VERSION 5.8 ;
BUSBITCHARS "[]" ;
DIVIDERCHAR "/" ;
 
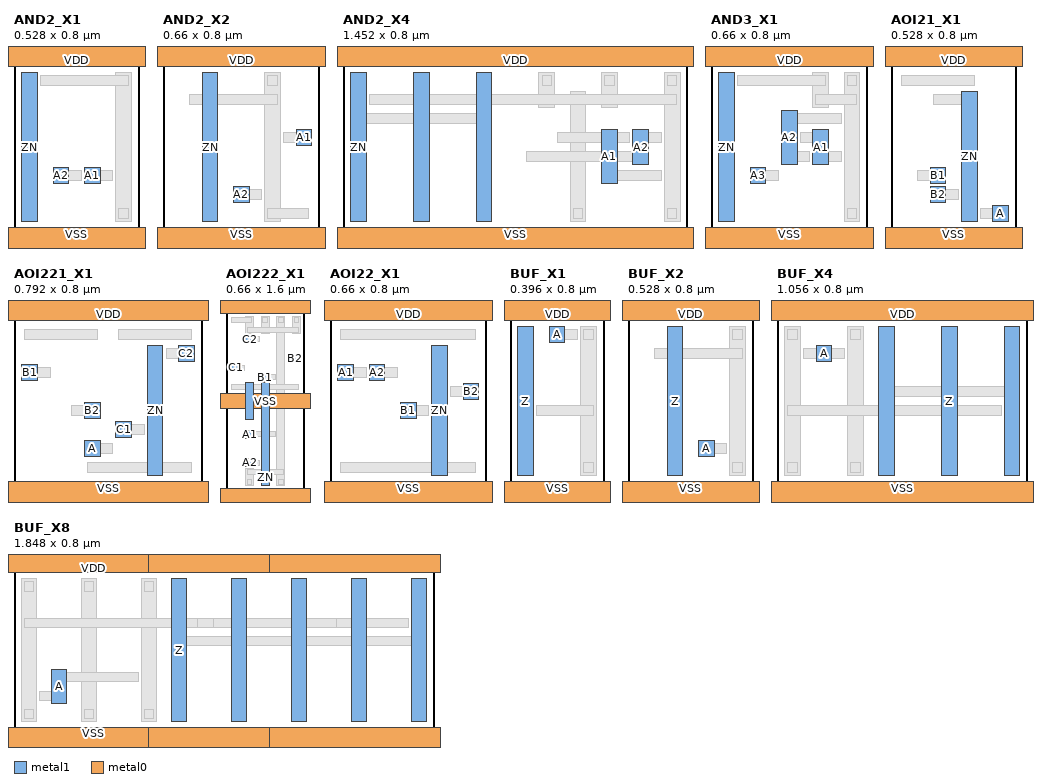
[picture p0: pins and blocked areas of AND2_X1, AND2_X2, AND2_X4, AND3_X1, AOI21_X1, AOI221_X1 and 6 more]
MACRO AND2_X1
  CLASS CORE ;
  FOREIGN AND2_X1 0 0 ;
  SIZE 0.528 BY 0.8 ;
  ORIGIN 0.0 0.0 ;
  SYMMETRY X Y ;
  PIN A1
    DIRECTION INPUT ;
    USE SIGNAL ;
    ANTENNAGATEAREA 0.008640 ;
    PORT
      LAYER metal1 ;
        RECT 0.297 0.247 0.363 0.313 ;
    END
  END A1
  PIN A2
    DIRECTION INPUT ;
    USE SIGNAL ;
    ANTENNAGATEAREA 0.008640 ;
    PORT
      LAYER metal1 ;
        RECT 0.165 0.247 0.231 0.313 ;
    END
  END A2
  PIN ZN
    DIRECTION OUTPUT ;
    USE SIGNAL ;
    ANTENNADIFFAREA 0.03888 ;
    PORT
      LAYER metal1 ;
        RECT 0.033 0.087 0.099 0.713 ;
    END
  END ZN
  PIN VDD
    DIRECTION INOUT ;
    USE POWER ;
    PORT
      LAYER metal0 ;
        RECT -0.066 0.74 0.594 0.86 ;
    END
  END VDD
  PIN VSS
    DIRECTION INOUT ;
    USE GROUND ;
    PORT
      LAYER metal0 ;
        RECT -0.066 -0.06 0.594 0.06 ;
    END
  END VSS
  OBS
    LAYER metal1 ;
      RECT 0.429 0.087 0.495 0.713 ;
    LAYER metal0 ;
      RECT 0.112 0.66 0.482 0.7 ;
      RECT 0.442 0.1 0.482 0.14 ;
      RECT 0.31 0.26 0.416 0.3 ;
      RECT 0.178 0.26 0.284 0.3 ;
      RECT 0.046 0.66 0.086 0.7 ;
      RECT 0.046 0.1 0.086 0.14 ;
  END
END AND2_X1

MACRO AND2_X2
  CLASS CORE ;
  FOREIGN AND2_X2 0 0 ;
  SIZE 0.66 BY 0.8 ;
  ORIGIN 0.0 0.0 ;
  SYMMETRY X Y ;
  PIN A1
    DIRECTION INPUT ;
    USE SIGNAL ;
    ANTENNAGATEAREA 0.008640 ;
    PORT
      LAYER metal1 ;
        RECT 0.561 0.407 0.627 0.473 ;
    END
  END A1
  PIN A2
    DIRECTION INPUT ;
    USE SIGNAL ;
    ANTENNAGATEAREA 0.008640 ;
    PORT
      LAYER metal1 ;
        RECT 0.297 0.167 0.363 0.233 ;
    END
  END A2
  PIN ZN
    DIRECTION OUTPUT ;
    USE SIGNAL ;
    ANTENNADIFFAREA 0.03888 ;
    PORT
      LAYER metal1 ;
        RECT 0.165 0.087 0.231 0.713 ;
    END
  END ZN
  PIN VDD
    DIRECTION INOUT ;
    USE POWER ;
    PORT
      LAYER metal0 ;
        RECT -0.066 0.74 0.726 0.86 ;
    END
  END VDD
  PIN VSS
    DIRECTION INOUT ;
    USE GROUND ;
    PORT
      LAYER metal0 ;
        RECT -0.066 -0.06 0.726 0.06 ;
    END
  END VSS
  OBS
    LAYER metal1 ;
      RECT 0.429 0.087 0.495 0.713 ;
    LAYER metal0 ;
      RECT 0.112 0.58 0.482 0.62 ;
      RECT 0.442 0.1 0.614 0.14 ;
      RECT 0.442 0.66 0.482 0.7 ;
      RECT 0.508 0.42 0.614 0.46 ;
      RECT 0.31 0.18 0.416 0.22 ;
      RECT 0.178 0.66 0.218 0.7 ;
      RECT 0.178 0.1 0.218 0.14 ;
  END
END AND2_X2

MACRO AND2_X4
  CLASS CORE ;
  FOREIGN AND2_X4 0 0 ;
  SIZE 1.452 BY 0.8 ;
  ORIGIN 0.0 0.0 ;
  SYMMETRY X Y ;
  PIN A1
    DIRECTION INPUT ;
    USE SIGNAL ;
    ANTENNAGATEAREA 0.017280 ;
    PORT
      LAYER metal1 ;
        RECT 1.089 0.247 1.155 0.473 ;
    END
  END A1
  PIN A2
    DIRECTION INPUT ;
    USE SIGNAL ;
    ANTENNAGATEAREA 0.017280 ;
    PORT
      LAYER metal1 ;
        RECT 1.221 0.327 1.287 0.473 ;
    END
  END A2
  PIN ZN
    DIRECTION OUTPUT ;
    USE SIGNAL ;
    ANTENNADIFFAREA 0.11664 ;
    PORT
      LAYER metal1 ;
        RECT 0.033 0.087 0.099 0.713 ;
        RECT 0.297 0.087 0.363 0.713 ;
        RECT 0.561 0.087 0.627 0.713 ;
    END
  END ZN
  PIN VDD
    DIRECTION INOUT ;
    USE POWER ;
    PORT
      LAYER metal0 ;
        RECT -0.066 0.74 1.518 0.86 ;
    END
  END VDD
  PIN VSS
    DIRECTION INOUT ;
    USE GROUND ;
    PORT
      LAYER metal0 ;
        RECT -0.066 -0.06 1.518 0.06 ;
    END
  END VSS
  OBS
    LAYER metal1 ;
      RECT 0.825 0.567 0.891 0.713 ;
      RECT 0.957 0.087 1.023 0.633 ;
      RECT 1.089 0.567 1.155 0.713 ;
      RECT 1.353 0.087 1.419 0.713 ;
    LAYER metal0 ;
      RECT 0.112 0.58 1.406 0.62 ;
      RECT 0.838 0.66 0.878 0.7 ;
      RECT 1.102 0.66 1.142 0.7 ;
      RECT 1.366 0.66 1.406 0.7 ;
      RECT 0.97 0.1 1.01 0.14 ;
      RECT 1.366 0.1 1.406 0.14 ;
      RECT 1.102 0.26 1.34 0.3 ;
      RECT 0.904 0.42 1.208 0.46 ;
      RECT 0.772 0.34 1.274 0.38 ;
      RECT 1.234 0.42 1.34 0.46 ;
      RECT 0.046 0.66 0.086 0.7 ;
      RECT 0.046 0.5 0.614 0.54 ;
      RECT 0.046 0.1 0.086 0.14 ;
      RECT 0.574 0.1 0.614 0.14 ;
      RECT 0.31 0.1 0.35 0.14 ;
      RECT 0.31 0.66 0.35 0.7 ;
      RECT 0.574 0.66 0.614 0.7 ;
  END
END AND2_X4

MACRO AND3_X1
  CLASS CORE ;
  FOREIGN AND3_X1 0 0 ;
  SIZE 0.66 BY 0.8 ;
  ORIGIN 0.0 0.0 ;
  SYMMETRY X Y ;
  PIN A1
    DIRECTION INPUT ;
    USE SIGNAL ;
    ANTENNAGATEAREA 0.008640 ;
    PORT
      LAYER metal1 ;
        RECT 0.429 0.327 0.495 0.473 ;
    END
  END A1
  PIN A2
    DIRECTION INPUT ;
    USE SIGNAL ;
    ANTENNAGATEAREA 0.008640 ;
    PORT
      LAYER metal1 ;
        RECT 0.297 0.327 0.363 0.553 ;
    END
  END A2
  PIN A3
    DIRECTION INPUT ;
    USE SIGNAL ;
    ANTENNAGATEAREA 0.008640 ;
    PORT
      LAYER metal1 ;
        RECT 0.165 0.247 0.231 0.313 ;
    END
  END A3
  PIN ZN
    DIRECTION OUTPUT ;
    USE SIGNAL ;
    ANTENNADIFFAREA 0.03888 ;
    PORT
      LAYER metal1 ;
        RECT 0.033 0.087 0.099 0.713 ;
    END
  END ZN
  PIN VDD
    DIRECTION INOUT ;
    USE POWER ;
    PORT
      LAYER metal0 ;
        RECT -0.066 0.74 0.726 0.86 ;
    END
  END VDD
  PIN VSS
    DIRECTION INOUT ;
    USE GROUND ;
    PORT
      LAYER metal0 ;
        RECT -0.066 -0.06 0.726 0.06 ;
    END
  END VSS
  OBS
    LAYER metal1 ;
      RECT 0.429 0.567 0.495 0.713 ;
      RECT 0.561 0.087 0.627 0.713 ;
    LAYER metal0 ;
      RECT 0.112 0.66 0.482 0.7 ;
      RECT 0.442 0.58 0.614 0.62 ;
      RECT 0.574 0.66 0.614 0.7 ;
      RECT 0.574 0.1 0.614 0.14 ;
      RECT 0.442 0.34 0.548 0.38 ;
      RECT 0.376 0.42 0.482 0.46 ;
      RECT 0.31 0.34 0.416 0.38 ;
      RECT 0.31 0.5 0.548 0.54 ;
      RECT 0.178 0.26 0.284 0.3 ;
      RECT 0.046 0.66 0.086 0.7 ;
      RECT 0.046 0.1 0.086 0.14 ;
  END
END AND3_X1

MACRO AOI21_X1
  CLASS CORE ;
  FOREIGN AOI21_X1 0 0 ;
  SIZE 0.528 BY 0.8 ;
  ORIGIN 0.0 0.0 ;
  SYMMETRY X Y ;
  PIN A
    DIRECTION INPUT ;
    USE SIGNAL ;
    ANTENNAGATEAREA 0.008640 ;
    PORT
      LAYER metal1 ;
        RECT 0.429 0.087 0.495 0.153 ;
    END
  END A
  PIN B1
    DIRECTION INPUT ;
    USE SIGNAL ;
    ANTENNAGATEAREA 0.008640 ;
    PORT
      LAYER metal1 ;
        RECT 0.165 0.247 0.231 0.313 ;
    END
  END B1
  PIN B2
    DIRECTION INPUT ;
    USE SIGNAL ;
    ANTENNAGATEAREA 0.008640 ;
    PORT
      LAYER metal1 ;
        RECT 0.165 0.167 0.231 0.233 ;
    END
  END B2
  PIN ZN
    DIRECTION OUTPUT ;
    USE SIGNAL ;
    ANTENNADIFFAREA 0.03888 ;
    PORT
      LAYER metal1 ;
        RECT 0.297 0.087 0.363 0.633 ;
    END
  END ZN
  PIN VDD
    DIRECTION INOUT ;
    USE POWER ;
    PORT
      LAYER metal0 ;
        RECT -0.066 0.74 0.594 0.86 ;
    END
  END VDD
  PIN VSS
    DIRECTION INOUT ;
    USE GROUND ;
    PORT
      LAYER metal0 ;
        RECT -0.066 -0.06 0.594 0.06 ;
    END
  END VSS
  OBS
    LAYER metal0 ;
      RECT 0.046 0.66 0.35 0.7 ;
      RECT 0.376 0.1 0.482 0.14 ;
      RECT 0.112 0.26 0.218 0.3 ;
      RECT 0.178 0.18 0.284 0.22 ;
      RECT 0.31 0.1 0.35 0.14 ;
      RECT 0.178 0.58 0.35 0.62 ;
  END
END AOI21_X1

MACRO AOI221_X1
  CLASS CORE ;
  FOREIGN AOI221_X1 0 0 ;
  SIZE 0.792 BY 0.8 ;
  ORIGIN 0.0 0.0 ;
  SYMMETRY X Y ;
  PIN A
    DIRECTION INPUT ;
    USE SIGNAL ;
    ANTENNAGATEAREA 0.008640 ;
    PORT
      LAYER metal1 ;
        RECT 0.297 0.167 0.363 0.233 ;
    END
  END A
  PIN B1
    DIRECTION INPUT ;
    USE SIGNAL ;
    ANTENNAGATEAREA 0.008640 ;
    PORT
      LAYER metal1 ;
        RECT 0.033 0.487 0.099 0.553 ;
    END
  END B1
  PIN B2
    DIRECTION INPUT ;
    USE SIGNAL ;
    ANTENNAGATEAREA 0.008640 ;
    PORT
      LAYER metal1 ;
        RECT 0.297 0.327 0.363 0.393 ;
    END
  END B2
  PIN C1
    DIRECTION INPUT ;
    USE SIGNAL ;
    ANTENNAGATEAREA 0.008640 ;
    PORT
      LAYER metal1 ;
        RECT 0.429 0.247 0.495 0.313 ;
    END
  END C1
  PIN C2
    DIRECTION INPUT ;
    USE SIGNAL ;
    ANTENNAGATEAREA 0.008640 ;
    PORT
      LAYER metal1 ;
        RECT 0.693 0.567 0.759 0.633 ;
    END
  END C2
  PIN ZN
    DIRECTION OUTPUT ;
    USE SIGNAL ;
    ANTENNADIFFAREA 0.05832 ;
    PORT
      LAYER metal1 ;
        RECT 0.561 0.087 0.627 0.633 ;
    END
  END ZN
  PIN VDD
    DIRECTION INOUT ;
    USE POWER ;
    PORT
      LAYER metal0 ;
        RECT -0.066 0.74 0.858 0.86 ;
    END
  END VDD
  PIN VSS
    DIRECTION INOUT ;
    USE GROUND ;
    PORT
      LAYER metal0 ;
        RECT -0.066 -0.06 0.858 0.06 ;
    END
  END VSS
  OBS
    LAYER metal0 ;
      RECT 0.442 0.66 0.746 0.7 ;
      RECT 0.046 0.66 0.35 0.7 ;
      RECT 0.31 0.18 0.416 0.22 ;
      RECT 0.046 0.5 0.152 0.54 ;
      RECT 0.244 0.34 0.35 0.38 ;
      RECT 0.442 0.26 0.548 0.3 ;
      RECT 0.64 0.58 0.746 0.62 ;
      RECT 0.31 0.1 0.746 0.14 ;
      RECT 0.574 0.58 0.614 0.62 ;
  END
END AOI221_X1

MACRO AOI222_X1
  CLASS CORE ;
  FOREIGN AOI222_X1 0 0 ;
  SIZE 0.66 BY 1.6 ;
  ORIGIN 0.0 0.0 ;
  SYMMETRY X Y ;
  PIN A1
    DIRECTION INPUT ;
    USE SIGNAL ;
    ANTENNAGATEAREA 0.008640 ;
    PORT
      LAYER metal1 ;
        RECT 0.165 0.487 0.231 0.553 ;
    END
  END A1
  PIN A2
    DIRECTION INPUT ;
    USE SIGNAL ;
    ANTENNAGATEAREA 0.008640 ;
    PORT
      LAYER metal1 ;
        RECT 0.165 0.247 0.231 0.313 ;
    END
  END A2
  PIN B1
    DIRECTION INPUT ;
    USE SIGNAL ;
    ANTENNAGATEAREA 0.008640 ;
    PORT
      LAYER metal1 ;
        RECT 0.297 0.967 0.363 1.033 ;
    END
  END B1
  PIN B2
    DIRECTION INPUT ;
    USE SIGNAL ;
    ANTENNAGATEAREA 0.008640 ;
    PORT
      LAYER metal1 ;
        RECT 0.561 1.127 0.627 1.193 ;
    END
  END B2
  PIN C1
    DIRECTION INPUT ;
    USE SIGNAL ;
    ANTENNAGATEAREA 0.008640 ;
    PORT
      LAYER metal1 ;
        RECT 0.033 1.047 0.099 1.113 ;
    END
  END C1
  PIN C2
    DIRECTION INPUT ;
    USE SIGNAL ;
    ANTENNAGATEAREA 0.008640 ;
    PORT
      LAYER metal1 ;
        RECT 0.165 1.287 0.231 1.353 ;
    END
  END C2
  PIN ZN
    DIRECTION OUTPUT ;
    USE SIGNAL ;
    ANTENNADIFFAREA 0.07776 ;
    PORT
      LAYER metal1 ;
        RECT 0.165 0.647 0.231 0.953 ;
        RECT 0.297 0.087 0.363 0.953 ;
    END
  END ZN
  PIN VDD
    DIRECTION INOUT ;
    USE POWER ;
    PORT
      LAYER metal0 ;
        RECT -0.066 -0.06 0.726 0.06 ;
        RECT -0.066 1.54 0.726 1.66 ;
    END
  END VDD
  PIN VSS
    DIRECTION INOUT ;
    USE GROUND ;
    PORT
      LAYER metal0 ;
        RECT -0.066 0.74 0.726 0.86 ;
    END
  END VSS
  OBS
    LAYER metal1 ;
      RECT 0.561 1.367 0.627 1.513 ;
      RECT 0.297 1.367 0.363 1.513 ;
      RECT 0.165 1.367 0.231 1.513 ;
      RECT 0.429 0.087 0.495 1.513 ;
      RECT 0.165 0.087 0.231 0.233 ;
    LAYER metal0 ;
      RECT 0.574 1.46 0.614 1.5 ;
      RECT 0.31 1.46 0.35 1.5 ;
      RECT 0.442 0.1 0.482 0.14 ;
      RECT 0.178 0.1 0.218 0.14 ;
      RECT 0.442 1.46 0.482 1.5 ;
      RECT 0.178 1.38 0.614 1.42 ;
      RECT 0.046 1.46 0.218 1.5 ;
      RECT 0.178 0.18 0.482 0.22 ;
      RECT 0.178 0.5 0.416 0.54 ;
      RECT 0.178 0.26 0.284 0.3 ;
      RECT 0.31 0.98 0.416 1.02 ;
      RECT 0.508 1.14 0.614 1.18 ;
      RECT 0.046 1.06 0.152 1.1 ;
      RECT 0.178 1.3 0.284 1.34 ;
      RECT 0.178 0.66 0.218 0.7 ;
      RECT 0.046 0.9 0.614 0.94 ;
      RECT 0.31 0.1 0.35 0.14 ;
  END
END AOI222_X1

MACRO AOI22_X1
  CLASS CORE ;
  FOREIGN AOI22_X1 0 0 ;
  SIZE 0.66 BY 0.8 ;
  ORIGIN 0.0 0.0 ;
  SYMMETRY X Y ;
  PIN A1
    DIRECTION INPUT ;
    USE SIGNAL ;
    ANTENNAGATEAREA 0.008640 ;
    PORT
      LAYER metal1 ;
        RECT 0.033 0.487 0.099 0.553 ;
    END
  END A1
  PIN A2
    DIRECTION INPUT ;
    USE SIGNAL ;
    ANTENNAGATEAREA 0.008640 ;
    PORT
      LAYER metal1 ;
        RECT 0.165 0.487 0.231 0.553 ;
    END
  END A2
  PIN B1
    DIRECTION INPUT ;
    USE SIGNAL ;
    ANTENNAGATEAREA 0.008640 ;
    PORT
      LAYER metal1 ;
        RECT 0.297 0.327 0.363 0.393 ;
    END
  END B1
  PIN B2
    DIRECTION INPUT ;
    USE SIGNAL ;
    ANTENNAGATEAREA 0.008640 ;
    PORT
      LAYER metal1 ;
        RECT 0.561 0.407 0.627 0.473 ;
    END
  END B2
  PIN ZN
    DIRECTION OUTPUT ;
    USE SIGNAL ;
    ANTENNADIFFAREA 0.05832 ;
    PORT
      LAYER metal1 ;
        RECT 0.429 0.087 0.495 0.633 ;
    END
  END ZN
  PIN VDD
    DIRECTION INOUT ;
    USE POWER ;
    PORT
      LAYER metal0 ;
        RECT -0.066 0.74 0.726 0.86 ;
    END
  END VDD
  PIN VSS
    DIRECTION INOUT ;
    USE GROUND ;
    PORT
      LAYER metal0 ;
        RECT -0.066 -0.06 0.726 0.06 ;
    END
  END VSS
  OBS
    LAYER metal0 ;
      RECT 0.046 0.66 0.614 0.7 ;
      RECT 0.046 0.5 0.152 0.54 ;
      RECT 0.178 0.5 0.284 0.54 ;
      RECT 0.31 0.34 0.416 0.38 ;
      RECT 0.508 0.42 0.614 0.46 ;
      RECT 0.442 0.58 0.482 0.62 ;
      RECT 0.046 0.1 0.614 0.14 ;
  END
END AOI22_X1

MACRO BUF_X1
  CLASS CORE ;
  FOREIGN BUF_X1 0 0 ;
  SIZE 0.396 BY 0.8 ;
  ORIGIN 0.0 0.0 ;
  SYMMETRY X Y ;
  PIN A
    DIRECTION INPUT ;
    USE SIGNAL ;
    ANTENNAGATEAREA 0.008640 ;
    PORT
      LAYER metal1 ;
        RECT 0.165 0.647 0.231 0.713 ;
    END
  END A
  PIN Z
    DIRECTION OUTPUT ;
    USE SIGNAL ;
    ANTENNADIFFAREA 0.03888 ;
    PORT
      LAYER metal1 ;
        RECT 0.033 0.087 0.099 0.713 ;
    END
  END Z
  PIN VDD
    DIRECTION INOUT ;
    USE POWER ;
    PORT
      LAYER metal0 ;
        RECT -0.066 0.74 0.462 0.86 ;
    END
  END VDD
  PIN VSS
    DIRECTION INOUT ;
    USE GROUND ;
    PORT
      LAYER metal0 ;
        RECT -0.066 -0.06 0.462 0.06 ;
    END
  END VSS
  OBS
    LAYER metal1 ;
      RECT 0.297 0.087 0.363 0.713 ;
    LAYER metal0 ;
      RECT 0.112 0.34 0.35 0.38 ;
      RECT 0.31 0.66 0.35 0.7 ;
      RECT 0.31 0.1 0.35 0.14 ;
      RECT 0.178 0.66 0.284 0.7 ;
      RECT 0.046 0.66 0.086 0.7 ;
      RECT 0.046 0.1 0.086 0.14 ;
  END
END BUF_X1

MACRO BUF_X2
  CLASS CORE ;
  FOREIGN BUF_X2 0 0 ;
  SIZE 0.528 BY 0.8 ;
  ORIGIN 0.0 0.0 ;
  SYMMETRY X Y ;
  PIN A
    DIRECTION INPUT ;
    USE SIGNAL ;
    ANTENNAGATEAREA 0.008640 ;
    PORT
      LAYER metal1 ;
        RECT 0.297 0.167 0.363 0.233 ;
    END
  END A
  PIN Z
    DIRECTION OUTPUT ;
    USE SIGNAL ;
    ANTENNADIFFAREA 0.03888 ;
    PORT
      LAYER metal1 ;
        RECT 0.165 0.087 0.231 0.713 ;
    END
  END Z
  PIN VDD
    DIRECTION INOUT ;
    USE POWER ;
    PORT
      LAYER metal0 ;
        RECT -0.066 0.74 0.594 0.86 ;
    END
  END VDD
  PIN VSS
    DIRECTION INOUT ;
    USE GROUND ;
    PORT
      LAYER metal0 ;
        RECT -0.066 -0.06 0.594 0.06 ;
    END
  END VSS
  OBS
    LAYER metal1 ;
      RECT 0.429 0.087 0.495 0.713 ;
    LAYER metal0 ;
      RECT 0.112 0.58 0.482 0.62 ;
      RECT 0.442 0.66 0.482 0.7 ;
      RECT 0.442 0.1 0.482 0.14 ;
      RECT 0.31 0.18 0.416 0.22 ;
      RECT 0.178 0.66 0.218 0.7 ;
      RECT 0.178 0.1 0.218 0.14 ;
  END
END BUF_X2

MACRO BUF_X4
  CLASS CORE ;
  FOREIGN BUF_X4 0 0 ;
  SIZE 1.056 BY 0.8 ;
  ORIGIN 0.0 0.0 ;
  SYMMETRY X Y ;
  PIN A
    DIRECTION INPUT ;
    USE SIGNAL ;
    ANTENNAGATEAREA 0.017280 ;
    PORT
      LAYER metal1 ;
        RECT 0.165 0.567 0.231 0.633 ;
    END
  END A
  PIN Z
    DIRECTION OUTPUT ;
    USE SIGNAL ;
    ANTENNADIFFAREA 0.11664 ;
    PORT
      LAYER metal1 ;
        RECT 0.429 0.087 0.495 0.713 ;
        RECT 0.693 0.087 0.759 0.713 ;
        RECT 0.957 0.087 1.023 0.713 ;
    END
  END Z
  PIN VDD
    DIRECTION INOUT ;
    USE POWER ;
    PORT
      LAYER metal0 ;
        RECT -0.066 0.74 1.122 0.86 ;
    END
  END VDD
  PIN VSS
    DIRECTION INOUT ;
    USE GROUND ;
    PORT
      LAYER metal0 ;
        RECT -0.066 -0.06 1.122 0.06 ;
    END
  END VSS
  OBS
    LAYER metal1 ;
      RECT 0.033 0.087 0.099 0.713 ;
      RECT 0.297 0.087 0.363 0.713 ;
    LAYER metal0 ;
      RECT 0.046 0.34 0.944 0.38 ;
      RECT 0.046 0.66 0.086 0.7 ;
      RECT 0.31 0.66 0.35 0.7 ;
      RECT 0.046 0.1 0.086 0.14 ;
      RECT 0.31 0.1 0.35 0.14 ;
      RECT 0.112 0.58 0.284 0.62 ;
      RECT 0.442 0.1 0.482 0.14 ;
      RECT 0.442 0.66 0.482 0.7 ;
      RECT 0.442 0.42 1.01 0.46 ;
      RECT 0.97 0.66 1.01 0.7 ;
      RECT 0.97 0.1 1.01 0.14 ;
      RECT 0.706 0.66 0.746 0.7 ;
      RECT 0.706 0.1 0.746 0.14 ;
  END
END BUF_X4

MACRO BUF_X8
  CLASS CORE ;
  FOREIGN BUF_X8 0 0 ;
  SIZE 1.848 BY 0.8 ;
  ORIGIN 0.0 0.0 ;
  SYMMETRY X Y ;
  PIN A
    DIRECTION INPUT ;
    USE SIGNAL ;
    ANTENNAGATEAREA 0.034560 ;
    PORT
      LAYER metal1 ;
        RECT 0.165 0.167 0.231 0.313 ;
    END
  END A
  PIN Z
    DIRECTION OUTPUT ;
    USE SIGNAL ;
    ANTENNADIFFAREA 0.19440 ;
    PORT
      LAYER metal1 ;
        RECT 1.749 0.087 1.815 0.713 ;
        RECT 1.221 0.087 1.287 0.713 ;
        RECT 0.693 0.087 0.759 0.713 ;
        RECT 0.957 0.087 1.023 0.713 ;
        RECT 1.485 0.087 1.551 0.713 ;
    END
  END Z
  PIN VDD
    DIRECTION INOUT ;
    USE POWER ;
    PORT
      LAYER metal0 ;
        RECT 1.122 0.74 1.914 0.86 ;
        RECT -0.066 0.74 0.726 0.86 ;
        RECT 0.594 0.74 1.386 0.86 ;
        RECT 1.122 0.74 1.914 0.86 ;
        RECT -0.066 0.74 0.726 0.86 ;
        RECT 0.594 0.74 1.386 0.86 ;
        RECT 1.122 0.74 1.914 0.86 ;
        RECT -0.066 0.74 0.726 0.86 ;
        RECT 0.594 0.74 1.386 0.86 ;
    END
  END VDD
  PIN VSS
    DIRECTION INOUT ;
    USE GROUND ;
    PORT
      LAYER metal0 ;
        RECT 0.594 -0.06 1.386 0.06 ;
        RECT -0.066 -0.06 0.726 0.06 ;
        RECT 1.122 -0.06 1.914 0.06 ;
        RECT 0.594 -0.06 1.386 0.06 ;
        RECT -0.066 -0.06 0.726 0.06 ;
        RECT 1.122 -0.06 1.914 0.06 ;
        RECT 0.594 -0.06 1.386 0.06 ;
        RECT -0.066 -0.06 0.726 0.06 ;
        RECT 1.122 -0.06 1.914 0.06 ;
    END
  END VSS
  OBS
    LAYER metal1 ;
      RECT 0.033 0.087 0.099 0.713 ;
      RECT 0.297 0.087 0.363 0.713 ;
      RECT 0.561 0.087 0.627 0.713 ;
    LAYER metal0 ;
      RECT 1.366 0.5 1.736 0.54 ;
      RECT 0.838 0.5 1.419 0.54 ;
      RECT 0.772 0.5 0.878 0.54 ;
      RECT 0.046 0.66 0.086 0.7 ;
      RECT 0.31 0.66 0.35 0.7 ;
      RECT 0.574 0.66 0.614 0.7 ;
      RECT 0.046 0.1 0.086 0.14 ;
      RECT 0.31 0.1 0.35 0.14 ;
      RECT 0.574 0.1 0.614 0.14 ;
      RECT 0.046 0.5 0.809 0.54 ;
      RECT 0.112 0.18 0.218 0.22 ;
      RECT 0.178 0.26 0.548 0.3 ;
      RECT 1.762 0.66 1.802 0.7 ;
      RECT 0.706 0.42 1.274 0.46 ;
      RECT 1.234 0.42 1.802 0.46 ;
      RECT 1.762 0.1 1.802 0.14 ;
      RECT 0.97 0.1 1.01 0.14 ;
      RECT 1.498 0.1 1.538 0.14 ;
      RECT 1.498 0.66 1.538 0.7 ;
      RECT 0.97 0.66 1.01 0.7 ;
      RECT 0.706 0.1 0.746 0.14 ;
      RECT 0.706 0.66 0.746 0.7 ;
      RECT 1.234 0.1 1.274 0.14 ;
      RECT 1.234 0.66 1.274 0.7 ;
  END
END BUF_X8

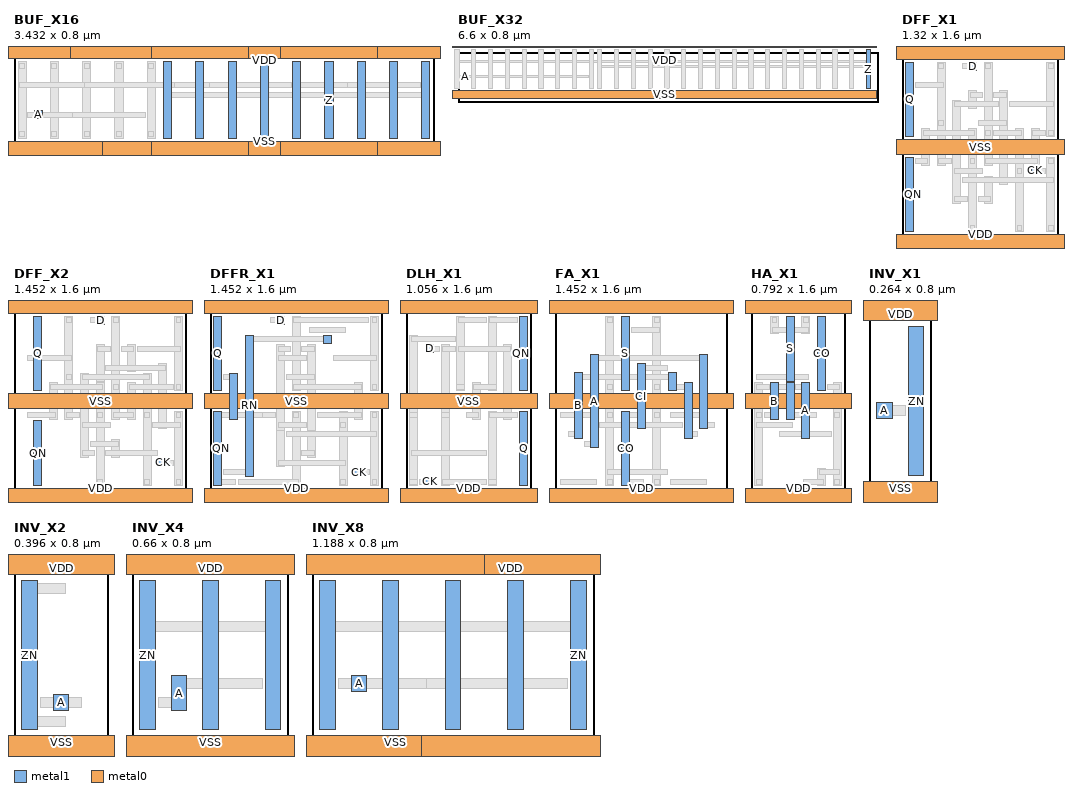
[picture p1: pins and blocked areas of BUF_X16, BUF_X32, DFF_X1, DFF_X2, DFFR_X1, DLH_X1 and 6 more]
MACRO BUF_X16
  CLASS CORE ;
  FOREIGN BUF_X16 0 0 ;
  SIZE 3.432 BY 0.8 ;
  ORIGIN 0.0 0.0 ;
  SYMMETRY X Y ;
  PIN A
    DIRECTION INPUT ;
    USE SIGNAL ;
    ANTENNAGATEAREA 0.069120 ;
    PORT
      LAYER metal1 ;
        RECT 0.165 0.247 0.231 0.313 ;
    END
  END A
  PIN Z
    DIRECTION OUTPUT ;
    USE SIGNAL ;
    ANTENNADIFFAREA 0.34992 ;
    PORT
      LAYER metal1 ;
        RECT 3.333 0.087 3.399 0.713 ;
        RECT 1.749 0.087 1.815 0.713 ;
        RECT 2.541 0.087 2.607 0.713 ;
        RECT 1.485 0.087 1.551 0.713 ;
        RECT 1.221 0.087 1.287 0.713 ;
        RECT 2.013 0.087 2.079 0.713 ;
        RECT 2.805 0.087 2.871 0.713 ;
        RECT 2.277 0.087 2.343 0.713 ;
        RECT 3.069 0.087 3.135 0.713 ;
    END
  END Z
  PIN VDD
    DIRECTION INOUT ;
    USE POWER ;
    PORT
      LAYER metal0 ;
        RECT 1.65 0.74 2.442 0.86 ;
        RECT 2.706 0.74 3.498 0.86 ;
        RECT -0.066 0.74 0.726 0.86 ;
        RECT 0.462 0.74 1.254 0.86 ;
        RECT 1.122 0.74 1.914 0.86 ;
        RECT 2.178 0.74 2.97 0.86 ;
    END
  END VDD
  PIN VSS
    DIRECTION INOUT ;
    USE GROUND ;
    PORT
      LAYER metal0 ;
        RECT 1.65 -0.06 2.442 0.06 ;
        RECT 0.462 -0.06 1.254 0.06 ;
        RECT 2.706 -0.06 3.498 0.06 ;
        RECT 2.178 -0.06 2.97 0.06 ;
        RECT -0.066 -0.06 0.726 0.06 ;
        RECT 1.122 -0.06 1.914 0.06 ;
    END
  END VSS
  OBS
    LAYER metal1 ;
      RECT 0.033 0.087 0.099 0.713 ;
      RECT 0.297 0.087 0.363 0.713 ;
      RECT 0.561 0.087 0.627 0.713 ;
      RECT 1.089 0.087 1.155 0.713 ;
      RECT 0.825 0.087 0.891 0.713 ;
    LAYER metal0 ;
      RECT 2.655 0.5 3.32 0.54 ;
      RECT 2.244 0.5 2.726 0.54 ;
      RECT 1.3 0.5 1.67 0.54 ;
      RECT 1.599 0.5 2.264 0.54 ;
      RECT 0.046 0.1 0.086 0.14 ;
      RECT 0.31 0.1 0.35 0.14 ;
      RECT 0.574 0.1 0.614 0.14 ;
      RECT 0.046 0.66 0.086 0.7 ;
      RECT 0.31 0.66 0.35 0.7 ;
      RECT 0.574 0.66 0.614 0.7 ;
      RECT 0.046 0.5 0.614 0.54 ;
      RECT 1.102 0.1 1.142 0.14 ;
      RECT 0.838 0.1 0.878 0.14 ;
      RECT 1.102 0.66 1.142 0.7 ;
      RECT 0.838 0.66 0.878 0.7 ;
      RECT 0.574 0.5 1.308 0.54 ;
      RECT 0.411 0.26 1.076 0.3 ;
      RECT 0.112 0.26 0.482 0.3 ;
      RECT 1.762 0.42 2.33 0.46 ;
      RECT 3.346 0.1 3.386 0.14 ;
      RECT 1.234 0.42 1.802 0.46 ;
      RECT 3.346 0.66 3.386 0.7 ;
      RECT 2.29 0.42 2.858 0.46 ;
      RECT 2.818 0.42 3.386 0.46 ;
      RECT 1.498 0.1 1.538 0.14 ;
      RECT 1.498 0.66 1.538 0.7 ;
      RECT 1.762 0.1 1.802 0.14 ;
      RECT 1.762 0.66 1.802 0.7 ;
      RECT 3.082 0.66 3.122 0.7 ;
      RECT 3.082 0.1 3.122 0.14 ;
      RECT 2.818 0.66 2.858 0.7 ;
      RECT 2.554 0.1 2.594 0.14 ;
      RECT 2.818 0.1 2.858 0.14 ;
      RECT 2.29 0.66 2.33 0.7 ;
      RECT 1.234 0.1 1.274 0.14 ;
      RECT 2.554 0.66 2.594 0.7 ;
      RECT 1.234 0.66 1.274 0.7 ;
      RECT 2.026 0.66 2.066 0.7 ;
      RECT 2.29 0.1 2.33 0.14 ;
      RECT 2.026 0.1 2.066 0.14 ;
  END
END BUF_X16

MACRO BUF_X32
  CLASS CORE ;
  ORIGIN 0 0 ;
  FOREIGN BUF_X32 0 0 ;
  SIZE 6.6 BY 0.8 ;
  PIN VDD
    DIRECTION INOUT ;
    USE POWER ;
    PORT
      LAYER metal0 ;
        RECT -0.148 0.858 6.584 0.978 ;
    END
  END VDD
  PIN VSS
    DIRECTION INOUT ;
    USE GROUND ;
    PORT
      LAYER metal0 ;
        RECT -0.148 0.058 6.584 0.178 ;
    END
  END VSS
  PIN A
    DIRECTION INOUT ;
    USE SIGNAL ;
    PORT
      LAYER metal1 ;
        RECT 0.083 0.365 0.149 0.431 ;
    END
  END A
  PIN Z
    DIRECTION INOUT ;
    USE SIGNAL ;
    PORT
      LAYER metal1 ;
        RECT 6.419 0.205 6.485 0.831 ;
    END
  END Z
  OBS
    LAYER metal0 SPACING 0 ;
      RECT -0.036 0.218 0.004 0.258 ;
      RECT 0.228 0.218 0.268 0.258 ;
      RECT 0.492 0.218 0.532 0.258 ;
      RECT 0.756 0.218 0.796 0.258 ;
      RECT 1.02 0.218 1.06 0.258 ;
      RECT 1.284 0.218 1.324 0.258 ;
      RECT 1.548 0.218 1.588 0.258 ;
      RECT 1.812 0.218 1.852 0.258 ;
      RECT 2.076 0.218 2.116 0.258 ;
      RECT 2.208 0.218 2.248 0.258 ;
      RECT 2.472 0.218 2.512 0.258 ;
      RECT 2.736 0.218 2.776 0.258 ;
      RECT 3 0.218 3.04 0.258 ;
      RECT 3.264 0.218 3.304 0.258 ;
      RECT 3.528 0.218 3.568 0.258 ;
      RECT 3.792 0.218 3.832 0.258 ;
      RECT 4.056 0.218 4.096 0.258 ;
      RECT 4.32 0.218 4.36 0.258 ;
      RECT 4.584 0.218 4.624 0.258 ;
      RECT 4.848 0.218 4.888 0.258 ;
      RECT 5.112 0.218 5.152 0.258 ;
      RECT 5.376 0.218 5.416 0.258 ;
      RECT 5.64 0.218 5.68 0.258 ;
      RECT 5.904 0.218 5.944 0.258 ;
      RECT 6.168 0.218 6.208 0.258 ;
      RECT 6.432 0.218 6.472 0.258 ;
      RECT 0.03 0.378 2.05 0.418 ;
      RECT 2.208 0.538 6.472 0.578 ;
      RECT -0.036 0.618 6.406 0.658 ;
      RECT -0.036 0.778 0.004 0.818 ;
      RECT 0.228 0.778 0.268 0.818 ;
      RECT 0.492 0.778 0.532 0.818 ;
      RECT 0.756 0.778 0.796 0.818 ;
      RECT 1.02 0.778 1.06 0.818 ;
      RECT 1.284 0.778 1.324 0.818 ;
      RECT 1.548 0.778 1.588 0.818 ;
      RECT 1.812 0.778 1.852 0.818 ;
      RECT 2.076 0.778 2.116 0.818 ;
      RECT 2.208 0.778 2.248 0.818 ;
      RECT 2.472 0.778 2.512 0.818 ;
      RECT 2.736 0.778 2.776 0.818 ;
      RECT 3 0.778 3.04 0.818 ;
      RECT 3.264 0.778 3.304 0.818 ;
      RECT 3.528 0.778 3.568 0.818 ;
      RECT 3.792 0.778 3.832 0.818 ;
      RECT 4.056 0.778 4.096 0.818 ;
      RECT 4.32 0.778 4.36 0.818 ;
      RECT 4.584 0.778 4.624 0.818 ;
      RECT 4.848 0.778 4.888 0.818 ;
      RECT 5.112 0.778 5.152 0.818 ;
      RECT 5.376 0.778 5.416 0.818 ;
      RECT 5.64 0.778 5.68 0.818 ;
      RECT 5.904 0.778 5.944 0.818 ;
      RECT 6.168 0.778 6.208 0.818 ;
      RECT 6.432 0.778 6.472 0.818 ;
    LAYER metal1 SPACING 0 ;
      RECT -0.049 0.205 0.017 0.831 ;
      RECT 0.215 0.205 0.281 0.831 ;
      RECT 0.479 0.205 0.545 0.831 ;
      RECT 0.743 0.205 0.809 0.831 ;
      RECT 1.007 0.205 1.073 0.831 ;
      RECT 1.271 0.205 1.337 0.831 ;
      RECT 1.535 0.205 1.601 0.831 ;
      RECT 1.799 0.205 1.865 0.831 ;
      RECT 2.063 0.205 2.129 0.831 ;
      RECT 2.195 0.205 2.261 0.831 ;
      RECT 2.459 0.205 2.525 0.831 ;
      RECT 2.723 0.205 2.789 0.831 ;
      RECT 2.987 0.205 3.053 0.831 ;
      RECT 3.251 0.205 3.317 0.831 ;
      RECT 3.515 0.205 3.581 0.831 ;
      RECT 3.779 0.205 3.845 0.831 ;
      RECT 4.043 0.205 4.109 0.831 ;
      RECT 4.307 0.205 4.373 0.831 ;
      RECT 4.571 0.205 4.637 0.831 ;
      RECT 4.835 0.205 4.901 0.831 ;
      RECT 5.099 0.205 5.165 0.831 ;
      RECT 5.363 0.205 5.429 0.831 ;
      RECT 5.627 0.205 5.693 0.831 ;
      RECT 5.891 0.205 5.957 0.831 ;
      RECT 6.155 0.205 6.221 0.831 ;
  END
END BUF_X32


MACRO DFF_X1
  CLASS CORE ;
  FOREIGN DFF_X1 0 0 ;
  SIZE 1.32 BY 1.6 ;
  ORIGIN 0.0 0.0 ;
  SYMMETRY X Y ;
  PIN CK
    DIRECTION INPUT ;
    USE CLOCK ;
    ANTENNAGATEAREA 0.008640 ;
    PORT
      LAYER metal1 ;
        RECT 1.089 0.567 1.155 0.633 ;
    END
  END CK
  PIN D
    DIRECTION INPUT ;
    USE SIGNAL ;
    ANTENNAGATEAREA 0.008640 ;
    PORT
      LAYER metal1 ;
        RECT 0.561 1.447 0.627 1.513 ;
    END
  END D
  PIN Q
    DIRECTION OUTPUT ;
    USE SIGNAL ;
    ANTENNADIFFAREA 0.03888 ;
    PORT
      LAYER metal1 ;
        RECT 0.033 0.887 0.099 1.513 ;
    END
  END Q
  PIN QN
    DIRECTION OUTPUT ;
    USE SIGNAL ;
    ANTENNADIFFAREA 0.03888 ;
    PORT
      LAYER metal1 ;
        RECT 0.033 0.087 0.099 0.713 ;
    END
  END QN
  PIN VDD
    DIRECTION INOUT ;
    USE POWER ;
    PORT
      LAYER metal0 ;
        RECT -0.066 1.54 1.386 1.66 ;
        RECT -0.066 -0.06 1.386 0.06 ;
    END
  END VDD
  PIN VSS
    DIRECTION INOUT ;
    USE GROUND ;
    PORT
      LAYER metal0 ;
        RECT -0.066 0.74 1.386 0.86 ;
    END
  END VSS
  OBS
    LAYER metal1 ;
      RECT 0.693 0.647 0.759 1.513 ;
      RECT 1.089 0.647 1.155 0.953 ;
      RECT 0.165 0.647 0.231 0.953 ;
      RECT 0.561 0.087 0.627 0.953 ;
      RECT 0.297 0.647 0.363 1.513 ;
      RECT 0.693 0.327 0.759 0.553 ;
      RECT 0.825 0.487 0.891 1.273 ;
      RECT 1.221 0.087 1.287 0.713 ;
      RECT 0.429 0.327 0.495 1.193 ;
      RECT 0.561 1.127 0.627 1.273 ;
      RECT 0.957 0.087 1.023 0.953 ;
      RECT 1.221 0.887 1.287 1.513 ;
    LAYER metal0 ;
      RECT 1.102 0.9 1.208 0.94 ;
      RECT 0.706 0.66 1.142 0.7 ;
      RECT 0.178 0.9 0.614 0.94 ;
      RECT 0.112 0.66 0.218 0.7 ;
      RECT 0.112 1.3 0.35 1.34 ;
      RECT 0.31 0.66 0.416 0.7 ;
      RECT 0.772 1.22 0.878 1.26 ;
      RECT 0.64 0.98 0.878 1.02 ;
      RECT 0.508 0.5 1.274 0.54 ;
      RECT 0.64 0.34 0.746 0.38 ;
      RECT 0.574 1.22 0.68 1.26 ;
      RECT 0.442 1.14 0.812 1.18 ;
      RECT 0.772 0.9 1.01 0.94 ;
      RECT 0.442 0.58 0.68 0.62 ;
      RECT 0.442 0.34 0.548 0.38 ;
      RECT 0.904 1.14 1.274 1.18 ;
      RECT 0.706 1.46 0.746 1.5 ;
      RECT 0.706 0.9 0.746 0.94 ;
      RECT 0.574 0.66 0.614 0.7 ;
      RECT 0.574 0.1 0.614 0.14 ;
      RECT 0.31 1.46 0.35 1.5 ;
      RECT 0.31 0.98 0.35 1.02 ;
      RECT 1.234 0.66 1.274 0.7 ;
      RECT 1.234 0.1 1.274 0.14 ;
      RECT 0.97 0.58 1.01 0.62 ;
      RECT 0.97 0.1 1.01 0.14 ;
      RECT 1.234 1.46 1.274 1.5 ;
      RECT 1.234 0.9 1.274 0.94 ;
      RECT 1.102 0.58 1.208 0.62 ;
      RECT 0.508 1.46 0.614 1.5 ;
      RECT 0.046 0.9 0.086 0.94 ;
      RECT 0.046 1.46 0.086 1.5 ;
      RECT 0.046 0.66 0.086 0.7 ;
      RECT 0.046 0.1 0.086 0.14 ;
  END
END DFF_X1

MACRO DFF_X2
  CLASS CORE ;
  FOREIGN DFF_X2 0 0 ;
  SIZE 1.452 BY 1.6 ;
  ORIGIN 0.0 0.0 ;
  SYMMETRY X Y ;
  PIN CK
    DIRECTION INPUT ;
    USE CLOCK ;
    ANTENNAGATEAREA 0.008640 ;
    PORT
      LAYER metal1 ;
        RECT 1.221 0.247 1.287 0.313 ;
    END
  END CK
  PIN D
    DIRECTION INPUT ;
    USE SIGNAL ;
    ANTENNAGATEAREA 0.008640 ;
    PORT
      LAYER metal1 ;
        RECT 0.693 1.447 0.759 1.513 ;
    END
  END D
  PIN Q
    DIRECTION OUTPUT ;
    USE SIGNAL ;
    ANTENNADIFFAREA 0.03888 ;
    PORT
      LAYER metal1 ;
        RECT 0.165 0.887 0.231 1.513 ;
    END
  END Q
  PIN QN
    DIRECTION OUTPUT ;
    USE SIGNAL ;
    ANTENNADIFFAREA 0.03888 ;
    PORT
      LAYER metal1 ;
        RECT 0.165 0.087 0.231 0.633 ;
    END
  END QN
  PIN VDD
    DIRECTION INOUT ;
    USE POWER ;
    PORT
      LAYER metal0 ;
        RECT -0.066 1.54 1.518 1.66 ;
        RECT -0.066 -0.06 1.518 0.06 ;
    END
  END VDD
  PIN VSS
    DIRECTION INOUT ;
    USE GROUND ;
    PORT
      LAYER metal0 ;
        RECT -0.066 0.74 1.518 0.86 ;
    END
  END VSS
  OBS
    LAYER metal1 ;
      RECT 0.297 0.647 0.363 0.953 ;
      RECT 0.693 0.087 0.759 0.953 ;
      RECT 0.825 0.647 0.891 1.513 ;
      RECT 0.957 0.647 1.023 0.953 ;
      RECT 0.561 0.327 0.627 1.033 ;
      RECT 0.693 0.967 0.759 1.273 ;
      RECT 1.089 0.087 1.155 1.033 ;
      RECT 1.353 0.887 1.419 1.513 ;
      RECT 0.429 0.647 0.495 1.513 ;
      RECT 0.825 0.327 0.891 0.473 ;
      RECT 0.957 1.047 1.023 1.273 ;
      RECT 1.221 0.567 1.287 1.113 ;
      RECT 1.353 0.087 1.419 0.713 ;
    LAYER metal0 ;
      RECT 0.31 0.9 0.746 0.94 ;
      RECT 0.112 0.66 0.35 0.7 ;
      RECT 0.97 0.9 1.34 0.94 ;
      RECT 0.838 0.66 1.01 0.7 ;
      RECT 0.706 1.22 0.812 1.26 ;
      RECT 0.574 0.98 1.142 1.02 ;
      RECT 0.574 0.58 0.812 0.62 ;
      RECT 0.574 0.34 0.68 0.38 ;
      RECT 1.036 1.22 1.406 1.26 ;
      RECT 0.112 1.14 0.482 1.18 ;
      RECT 0.442 0.66 0.548 0.7 ;
      RECT 0.904 1.22 1.01 1.26 ;
      RECT 0.772 1.06 1.274 1.1 ;
      RECT 1.168 0.58 1.406 0.62 ;
      RECT 0.64 0.42 0.878 0.46 ;
      RECT 0.772 0.34 1.208 0.38 ;
      RECT 0.706 0.66 0.746 0.7 ;
      RECT 0.706 0.1 0.746 0.14 ;
      RECT 0.838 1.46 0.878 1.5 ;
      RECT 0.838 0.9 0.878 0.94 ;
      RECT 1.102 0.66 1.142 0.7 ;
      RECT 1.102 0.1 1.142 0.14 ;
      RECT 1.366 1.46 1.406 1.5 ;
      RECT 1.366 0.9 1.406 0.94 ;
      RECT 0.442 1.46 0.482 1.5 ;
      RECT 0.442 0.98 0.482 1.02 ;
      RECT 1.366 0.66 1.406 0.7 ;
      RECT 1.366 0.1 1.406 0.14 ;
      RECT 1.234 0.26 1.34 0.3 ;
      RECT 0.64 1.46 0.746 1.5 ;
      RECT 0.178 0.9 0.218 0.94 ;
      RECT 0.178 1.46 0.218 1.5 ;
      RECT 0.178 0.1 0.218 0.14 ;
      RECT 0.178 0.58 0.218 0.62 ;
  END
END DFF_X2

MACRO DFFR_X1
  CLASS CORE ;
  FOREIGN DFFR_X1 0 0 ;
  SIZE 1.452 BY 1.6 ;
  ORIGIN 0.0 0.0 ;
  SYMMETRY X Y ;
  PIN CK
    DIRECTION INPUT ;
    USE CLOCK ;
    ANTENNAGATEAREA 0.008640 ;
    PORT
      LAYER metal1 ;
        RECT 1.221 0.167 1.287 0.233 ;
    END
  END CK
  PIN D
    DIRECTION INPUT ;
    USE SIGNAL ;
    ANTENNAGATEAREA 0.008640 ;
    PORT
      LAYER metal1 ;
        RECT 0.561 1.447 0.627 1.513 ;
    END
  END D
  PIN Q
    DIRECTION OUTPUT ;
    USE SIGNAL ;
    ANTENNADIFFAREA 0.03888 ;
    PORT
      LAYER metal1 ;
        RECT 0.033 0.887 0.099 1.513 ;
    END
  END Q
  PIN QN
    DIRECTION OUTPUT ;
    USE SIGNAL ;
    ANTENNAGATEAREA 0.017280 ;
    ANTENNADIFFAREA 0.03888 ;
    PORT
      LAYER metal1 ;
        RECT 0.033 0.087 0.099 0.713 ;
        RECT 0.165 0.647 0.231 1.033 ;
    END
  END QN
  PIN RN
    DIRECTION INPUT ;
    USE SIGNAL ;
    ANTENNAGATEAREA 0.017280 ;
    PORT
      LAYER metal1 ;
        RECT 0.957 1.287 1.023 1.353 ;
        RECT 0.297 0.167 0.363 1.353 ;
    END
  END RN
  PIN VDD
    DIRECTION INOUT ;
    USE POWER ;
    PORT
      LAYER metal0 ;
        RECT -0.066 -0.06 1.518 0.06 ;
        RECT -0.066 1.54 1.518 1.66 ;
    END
  END VDD
  PIN VSS
    DIRECTION INOUT ;
    USE GROUND ;
    PORT
      LAYER metal0 ;
        RECT -0.066 0.74 1.518 0.86 ;
    END
  END VSS
  OBS
    LAYER metal1 ;
      RECT 0.693 0.887 0.759 1.513 ;
      RECT 0.561 0.247 0.627 0.633 ;
      RECT 0.825 0.459 0.891 1.273 ;
      RECT 1.353 0.087 1.419 0.713 ;
      RECT 0.825 0.327 0.891 0.553 ;
      RECT 1.353 0.887 1.419 1.513 ;
      RECT 0.561 0.553 0.627 1.273 ;
      RECT 1.089 0.087 1.155 0.713 ;
      RECT 1.221 0.647 1.287 0.953 ;
      RECT 0.693 0.087 0.759 0.713 ;
    LAYER metal0 ;
      RECT 1.366 1.46 1.406 1.5 ;
      RECT 1.366 0.9 1.406 0.94 ;
      RECT 0.64 0.5 1.406 0.54 ;
      RECT 0.904 0.66 1.274 0.7 ;
      RECT 0.574 0.58 0.812 0.62 ;
      RECT 0.772 0.34 0.878 0.38 ;
      RECT 0.574 0.26 1.143 0.3 ;
      RECT 0.706 0.66 0.746 0.7 ;
      RECT 0.244 0.1 0.746 0.14 ;
      RECT 1.366 0.66 1.406 0.7 ;
      RECT 1.366 0.1 1.406 0.14 ;
      RECT 1.102 0.58 1.142 0.62 ;
      RECT 1.102 0.1 1.142 0.14 ;
      RECT 1.036 1.14 1.406 1.18 ;
      RECT 0.64 0.98 0.878 1.02 ;
      RECT 0.772 1.22 0.878 1.26 ;
      RECT 0.574 1.22 0.68 1.26 ;
      RECT 0.706 1.46 1.332 1.5 ;
      RECT 0.706 0.9 1.274 0.94 ;
      RECT 0.838 1.38 1.143 1.42 ;
      RECT 0.574 1.14 0.811 1.18 ;
      RECT 1.234 0.18 1.34 0.22 ;
      RECT 0.508 1.46 0.614 1.5 ;
      RECT 0.046 0.9 0.086 0.94 ;
      RECT 0.046 1.46 0.086 1.5 ;
      RECT 0.046 0.66 0.482 0.7 ;
      RECT 0.046 0.1 0.218 0.14 ;
      RECT 0.442 0.66 0.548 0.7 ;
      RECT 0.112 0.98 0.218 1.02 ;
      RECT 0.31 1.3 1.011 1.34 ;
      RECT 0.112 0.18 0.35 0.22 ;
  END
END DFFR_X1

MACRO DLH_X1
  CLASS CORE ;
  FOREIGN DLH_X1 0 0 ;
  SIZE 1.056 BY 1.6 ;
  ORIGIN 0.0 0.0 ;
  SYMMETRY X Y ;
  PIN CK
    DIRECTION INPUT ;
    USE CLOCK ;
    ANTENNAGATEAREA 0.008640 ;
    PORT
      LAYER metal1 ;
        RECT 0.165 0.087 0.231 0.153 ;
    END
  END CK
  PIN D
    DIRECTION INPUT ;
    USE SIGNAL ;
    ANTENNAGATEAREA 0.008640 ;
    PORT
      LAYER metal1 ;
        RECT 0.165 1.207 0.231 1.273 ;
    END
  END D
  PIN Q
    DIRECTION OUTPUT ;
    USE SIGNAL ;
    ANTENNADIFFAREA 0.03888 ;
    PORT
      LAYER metal1 ;
        RECT 0.957 0.087 1.023 0.713 ;
    END
  END Q
  PIN QN
    DIRECTION OUTPUT ;
    USE SIGNAL ;
    ANTENNADIFFAREA 0.03888 ;
    PORT
      LAYER metal1 ;
        RECT 0.957 0.887 1.023 1.513 ;
    END
  END QN
  PIN VDD
    DIRECTION INOUT ;
    USE POWER ;
    PORT
      LAYER metal0 ;
        RECT -0.066 -0.06 1.122 0.06 ;
        RECT -0.066 1.54 1.122 1.66 ;
    END
  END VDD
  PIN VSS
    DIRECTION INOUT ;
    USE GROUND ;
    PORT
      LAYER metal0 ;
        RECT -0.066 0.74 1.122 0.86 ;
    END
  END VSS
  OBS
    LAYER metal1 ;
      RECT 0.297 0.087 0.363 1.273 ;
      RECT 0.693 0.087 0.759 0.713 ;
      RECT 0.033 0.087 0.099 1.353 ;
      RECT 0.825 0.647 0.891 1.273 ;
      RECT 0.561 0.642 0.627 0.953 ;
      RECT 0.693 0.887 0.759 1.513 ;
      RECT 0.429 0.887 0.495 1.513 ;
    LAYER metal0 ;
      RECT 0.565 0.9 0.759 0.94 ;
      RECT 0.693 0.1 0.759 0.14 ;
      RECT 0.297 0.66 0.363 0.7 ;
      RECT 0.31 0.1 0.679 0.14 ;
      RECT 0.706 0.66 0.941 0.7 ;
      RECT 0.033 0.66 0.099 0.7 ;
      RECT 0.429 0.9 0.495 0.94 ;
      RECT 0.046 1.3 0.416 1.34 ;
      RECT 0.442 1.22 0.88 1.26 ;
      RECT 0.509 0.66 0.614 0.7 ;
      RECT 0.033 0.1 0.099 0.14 ;
      RECT 0.706 1.46 0.943 1.5 ;
      RECT 0.31 1.22 0.416 1.26 ;
      RECT 0.442 1.46 0.678 1.5 ;
      RECT 0.046 0.34 0.679 0.38 ;
      RECT 0.112 0.1 0.23 0.14 ;
      RECT 0.178 1.22 0.284 1.26 ;
      RECT 0.957 0.66 1.023 0.7 ;
      RECT 0.957 0.1 1.023 0.14 ;
      RECT 0.957 0.9 1.023 0.94 ;
      RECT 0.957 1.46 1.023 1.5 ;
  END
END DLH_X1

MACRO FA_X1
  CLASS CORE ;
  FOREIGN FA_X1 0 0 ;
  SIZE 1.452 BY 1.6 ;
  ORIGIN 0.0 0.0 ;
  SYMMETRY X Y ;
  PIN A
    DIRECTION INPUT ;
    USE SIGNAL ;
    ANTENNAGATEAREA 0.034560 ;
    PORT
      LAYER metal1 ;
        RECT 0.297 0.407 0.363 1.193 ;
        RECT 1.219 0.567 1.285 1.193 ;
    END
  END A
  PIN B
    DIRECTION INPUT ;
    USE SIGNAL ;
    ANTENNAGATEAREA 0.034560 ;
    PORT
      LAYER metal1 ;
        RECT 0.165 0.487 0.231 1.039 ;
        RECT 0.957 0.887 1.023 1.039 ;
        RECT 1.089 0.487 1.155 0.953 ;
    END
  END B
  PIN CI
    DIRECTION INPUT ;
    USE SIGNAL ;
    ANTENNAGATEAREA 0.025920 ;
    PORT
      LAYER metal1 ;
        RECT 0.693 0.567 0.759 1.113 ;
    END
  END CI
  PIN CO
    DIRECTION OUTPUT ;
    USE SIGNAL ;
    ANTENNADIFFAREA 0.03888 ;
    PORT
      LAYER metal1 ;
        RECT 0.561 0.087 0.627 0.713 ;
    END
  END CO
  PIN S
    DIRECTION INPUT ;
    USE SIGNAL ;
    ANTENNADIFFAREA 0.03888 ;
    PORT
      LAYER metal1 ;
        RECT 0.56 0.887 0.626 1.513 ;
    END
  END S
  PIN VDD
    DIRECTION INOUT ;
    USE POWER ;
    PORT
      LAYER metal0 ;
        RECT -0.066 -0.06 1.518 0.06 ;
        RECT -0.066 1.54 1.518 1.66 ;
    END
  END VDD
  PIN VSS
    DIRECTION INOUT ;
    USE GROUND ;
    PORT
      LAYER metal0 ;
        RECT -0.066 0.74 1.518 0.86 ;
    END
  END VSS
  OBS
    LAYER metal1 ;
      RECT 0.825 0.087 0.891 1.513 ;
      RECT 0.429 0.087 0.495 1.513 ;
    LAYER metal0 ;
      RECT 0.046 0.66 0.35 0.7 ;
      RECT 0.97 0.66 1.274 0.7 ;
      RECT 0.838 0.66 0.878 0.7 ;
      RECT 0.838 1.46 0.878 1.5 ;
      RECT 0.442 1.46 0.482 1.5 ;
      RECT 0.838 0.1 0.878 0.14 ;
      RECT 0.046 0.1 0.35 0.14 ;
      RECT 0.97 0.1 1.274 0.14 ;
      RECT 0.442 0.66 0.482 0.7 ;
      RECT 0.64 1.38 0.878 1.42 ;
      RECT 0.442 0.1 0.482 0.14 ;
      RECT 0.442 0.18 0.944 0.22 ;
      RECT 0.838 0.9 0.878 0.94 ;
      RECT 0.442 0.9 0.482 0.94 ;
      RECT 0.25 0.42 0.35 0.46 ;
      RECT 0.31 1.14 1.272 1.18 ;
      RECT 1.233 0.58 1.34 0.62 ;
      RECT 0.112 0.5 0.218 0.54 ;
      RECT 0.178 0.98 1.01 1.02 ;
      RECT 0.97 0.9 1.142 0.94 ;
      RECT 1.102 0.5 1.203 0.54 ;
      RECT 0.705 1.06 0.944 1.1 ;
      RECT 0.376 0.58 1.076 0.62 ;
      RECT 0.574 0.66 0.746 0.7 ;
      RECT 0.574 0.1 0.746 0.14 ;
      RECT 0.574 1.46 0.614 1.5 ;
      RECT 0.574 0.9 0.614 0.94 ;
  END
END FA_X1

MACRO HA_X1
  CLASS CORE ;
  FOREIGN HA_X1 0 0 ;
  SIZE 0.792 BY 1.6 ;
  ORIGIN 0.0 0.0 ;
  SYMMETRY X Y ;
  PIN A
    DIRECTION INPUT ;
    USE SIGNAL ;
    ANTENNAGATEAREA 0.025920 ;
    PORT
      LAYER metal1 ;
        RECT 0.429 0.487 0.495 0.953 ;
    END
  END A
  PIN B
    DIRECTION INPUT ;
    USE SIGNAL ;
    ANTENNAGATEAREA 0.025920 ;
    PORT
      LAYER metal1 ;
        RECT 0.165 0.647 0.231 0.953 ;
        RECT 0.297 0.647 0.363 0.953 ;
    END
  END B
  PIN CO
    DIRECTION OUTPUT ;
    USE SIGNAL ;
    ANTENNADIFFAREA 0.03888 ;
    PORT
      LAYER metal1 ;
        RECT 0.561 0.887 0.627 1.513 ;
    END
  END CO
  PIN S
    DIRECTION INPUT ;
    USE SIGNAL ;
    ANTENNADIFFAREA 0.05832 ;
    PORT
      LAYER metal1 ;
        RECT 0.297 0.967 0.363 1.513 ;
    END
  END S
  PIN VDD
    DIRECTION INOUT ;
    USE POWER ;
    PORT
      LAYER metal0 ;
        RECT -0.066 1.54 0.858 1.66 ;
        RECT -0.066 -0.06 0.858 0.06 ;
    END
  END VDD
  PIN VSS
    DIRECTION INOUT ;
    USE GROUND ;
    PORT
      LAYER metal0 ;
        RECT -0.066 0.74 0.858 0.86 ;
    END
  END VSS
  OBS
    LAYER metal1 ;
      RECT 0.033 0.087 0.099 0.953 ;
      RECT 0.561 0.087 0.627 0.233 ;
      RECT 0.693 0.087 0.759 0.953 ;
      RECT 0.165 1.367 0.231 1.513 ;
      RECT 0.429 1.367 0.495 1.513 ;
    LAYER metal0 ;
      RECT 0.046 0.9 0.152 0.94 ;
      RECT 0.046 0.58 0.35 0.62 ;
      RECT 0.64 0.9 0.746 0.94 ;
      RECT 0.574 0.18 0.746 0.22 ;
      RECT 0.442 0.1 0.614 0.14 ;
      RECT 0.178 1.38 0.482 1.42 ;
      RECT 0.046 0.66 0.086 0.7 ;
      RECT 0.046 0.1 0.086 0.14 ;
      RECT 0.706 0.66 0.746 0.7 ;
      RECT 0.706 0.1 0.746 0.14 ;
      RECT 0.178 1.46 0.218 1.5 ;
      RECT 0.442 1.46 0.482 1.5 ;
      RECT 0.244 0.5 0.68 0.54 ;
      RECT 0.376 0.9 0.482 0.94 ;
      RECT 0.178 0.9 0.35 0.94 ;
      RECT 0.112 0.66 0.218 0.7 ;
      RECT 0.31 0.66 0.548 0.7 ;
      RECT 0.574 1.46 0.614 1.5 ;
      RECT 0.574 0.9 0.614 0.94 ;
      RECT 0.31 1.46 0.35 1.5 ;
      RECT 0.046 0.98 0.482 1.02 ;
  END
END HA_X1

MACRO INV_X1
  CLASS CORE ;
  FOREIGN INV_X1 0 0 ;
  SIZE 0.264 BY 0.8 ;
  ORIGIN 0.0 0.0 ;
  SYMMETRY X Y ;
  PIN A
    DIRECTION INPUT ;
    USE SIGNAL ;
    ANTENNAGATEAREA 0.008640 ;
    PORT
      LAYER metal1 ;
        RECT 0.033 0.327 0.099 0.393 ;
    END
  END A
  PIN ZN
    DIRECTION OUTPUT ;
    USE SIGNAL ;
    ANTENNADIFFAREA 0.03888 ;
    PORT
      LAYER metal1 ;
        RECT 0.165 0.087 0.231 0.713 ;
    END
  END ZN
  PIN VDD
    DIRECTION INOUT ;
    USE POWER ;
    PORT
      LAYER metal0 ;
        RECT -0.066 0.74 0.33 0.86 ;
    END
  END VDD
  PIN VSS
    DIRECTION INOUT ;
    USE GROUND ;
    PORT
      LAYER metal0 ;
        RECT -0.066 -0.06 0.33 0.06 ;
    END
  END VSS
  OBS
    LAYER metal0 ;
      RECT 0.046 0.34 0.152 0.38 ;
      RECT 0.178 0.66 0.218 0.7 ;
      RECT 0.178 0.1 0.218 0.14 ;
  END
END INV_X1

MACRO INV_X2
  CLASS CORE ;
  FOREIGN INV_X2 0 0 ;
  SIZE 0.396 BY 0.8 ;
  ORIGIN 0.0 0.0 ;
  SYMMETRY X Y ;
  PIN A
    DIRECTION INPUT ;
    USE SIGNAL ;
    ANTENNAGATEAREA 0.017280 ;
    PORT
      LAYER metal1 ;
        RECT 0.165 0.167 0.231 0.233 ;
    END
  END A
  PIN ZN
    DIRECTION OUTPUT ;
    USE SIGNAL ;
    ANTENNADIFFAREA 0.03888 ;
    PORT
      LAYER metal1 ;
        RECT 0.033 0.087 0.099 0.713 ;
    END
  END ZN
  PIN VDD
    DIRECTION INOUT ;
    USE POWER ;
    PORT
      LAYER metal0 ;
        RECT -0.066 0.74 0.462 0.86 ;
    END
  END VDD
  PIN VSS
    DIRECTION INOUT ;
    USE GROUND ;
    PORT
      LAYER metal0 ;
        RECT -0.066 -0.06 0.462 0.06 ;
    END
  END VSS
  OBS
    LAYER metal0 ;
      RECT 0.112 0.18 0.284 0.22 ;
      RECT 0.046 0.1 0.218 0.14 ;
      RECT 0.046 0.66 0.218 0.7 ;
  END
END INV_X2

MACRO INV_X4
  CLASS CORE ;
  FOREIGN INV_X4 0 0 ;
  SIZE 0.66 BY 0.8 ;
  ORIGIN 0.0 0.0 ;
  SYMMETRY X Y ;
  PIN A
    DIRECTION INPUT ;
    USE SIGNAL ;
    ANTENNAGATEAREA 0.034560 ;
    PORT
      LAYER metal1 ;
        RECT 0.165 0.167 0.231 0.313 ;
    END
  END A
  PIN ZN
    DIRECTION OUTPUT ;
    USE SIGNAL ;
    ANTENNADIFFAREA 0.11664 ;
    PORT
      LAYER metal1 ;
        RECT 0.033 0.087 0.099 0.713 ;
        RECT 0.297 0.087 0.363 0.713 ;
        RECT 0.561 0.087 0.627 0.713 ;
    END
  END ZN
  PIN VDD
    DIRECTION INOUT ;
    USE POWER ;
    PORT
      LAYER metal0 ;
        RECT -0.066 0.74 0.726 0.86 ;
    END
  END VDD
  PIN VSS
    DIRECTION INOUT ;
    USE GROUND ;
    PORT
      LAYER metal0 ;
        RECT -0.066 -0.06 0.726 0.06 ;
    END
  END VSS
  OBS
    LAYER metal0 ;
      RECT 0.112 0.18 0.218 0.22 ;
      RECT 0.178 0.26 0.548 0.3 ;
      RECT 0.046 0.66 0.086 0.7 ;
      RECT 0.046 0.5 0.614 0.54 ;
      RECT 0.046 0.1 0.086 0.14 ;
      RECT 0.574 0.1 0.614 0.14 ;
      RECT 0.31 0.1 0.35 0.14 ;
      RECT 0.31 0.66 0.35 0.7 ;
      RECT 0.574 0.66 0.614 0.7 ;
  END
END INV_X4

MACRO INV_X8
  CLASS CORE ;
  FOREIGN INV_X8 0 0 ;
  SIZE 1.188 BY 0.8 ;
  ORIGIN 0.0 0.0 ;
  SYMMETRY X Y ;
  PIN A
    DIRECTION INPUT ;
    USE SIGNAL ;
    ANTENNAGATEAREA 0.069120 ;
    PORT
      LAYER metal1 ;
        RECT 0.165 0.247 0.231 0.313 ;
    END
  END A
  PIN ZN
    DIRECTION OUTPUT ;
    USE SIGNAL ;
    ANTENNADIFFAREA 0.19440 ;
    PORT
      LAYER metal1 ;
        RECT 0.561 0.087 0.627 0.713 ;
        RECT 0.297 0.087 0.363 0.713 ;
        RECT 0.033 0.087 0.099 0.713 ;
        RECT 1.089 0.087 1.155 0.713 ;
        RECT 0.825 0.087 0.891 0.713 ;
    END
  END ZN
  PIN VDD
    DIRECTION INOUT ;
    USE POWER ;
    PORT
      LAYER metal0 ;
        RECT 0.462 0.74 1.254 0.86 ;
        RECT -0.066 0.74 0.726 0.86 ;
    END
  END VDD
  PIN VSS
    DIRECTION INOUT ;
    USE GROUND ;
    PORT
      LAYER metal0 ;
        RECT -0.066 -0.06 0.726 0.06 ;
        RECT 0.462 -0.06 1.254 0.06 ;
    END
  END VSS
  OBS
    LAYER metal0 ;
      RECT 0.411 0.26 1.076 0.3 ;
      RECT 0.112 0.26 0.482 0.3 ;
      RECT 0.574 0.5 1.142 0.54 ;
      RECT 0.574 0.1 0.614 0.14 ;
      RECT 0.046 0.5 0.614 0.54 ;
      RECT 0.574 0.66 0.614 0.7 ;
      RECT 0.046 0.66 0.086 0.7 ;
      RECT 0.31 0.1 0.35 0.14 ;
      RECT 1.102 0.1 1.142 0.14 ;
      RECT 0.31 0.66 0.35 0.7 ;
      RECT 1.102 0.66 1.142 0.7 ;
      RECT 0.046 0.1 0.086 0.14 ;
      RECT 0.838 0.66 0.878 0.7 ;
      RECT 0.838 0.1 0.878 0.14 ;
  END
END INV_X8

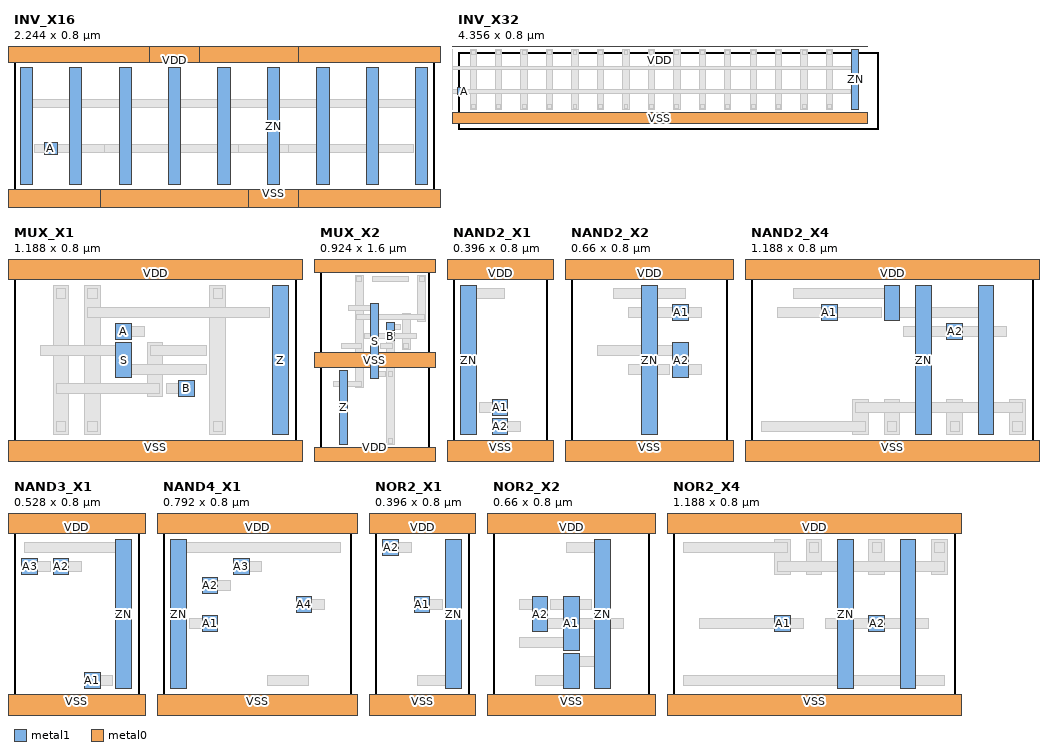
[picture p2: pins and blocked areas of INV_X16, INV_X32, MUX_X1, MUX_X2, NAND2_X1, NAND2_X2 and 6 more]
MACRO INV_X16
  CLASS CORE ;
  FOREIGN INV_X16 0 0 ;
  SIZE 2.244 BY 0.8 ;
  ORIGIN 0.0 0.0 ;
  SYMMETRY X Y ;
  PIN A
    DIRECTION INPUT ;
    USE SIGNAL ;
    ANTENNAGATEAREA 0.138240 ;
    PORT
      LAYER metal1 ;
        RECT 0.164 0.247 0.23 0.313 ;
    END
  END A
  PIN ZN
    DIRECTION OUTPUT ;
    USE SIGNAL ;
    ANTENNADIFFAREA 0.34992 ;
    PORT
      LAYER metal1 ;
        RECT 2.145 0.087 2.211 0.713 ;
        RECT 0.297 0.087 0.363 0.713 ;
        RECT 1.353 0.087 1.419 0.713 ;
        RECT 1.881 0.087 1.947 0.713 ;
        RECT 0.033 0.087 0.099 0.713 ;
        RECT 1.089 0.087 1.155 0.713 ;
        RECT 0.825 0.087 0.891 0.713 ;
        RECT 0.561 0.087 0.627 0.713 ;
        RECT 1.617 0.087 1.683 0.713 ;
    END
  END ZN
  PIN VDD
    DIRECTION INOUT ;
    USE POWER ;
    PORT
      LAYER metal0 ;
        RECT 0.462 0.74 1.254 0.86 ;
        RECT -0.066 0.74 0.726 0.86 ;
        RECT 0.99 0.74 1.782 0.86 ;
        RECT 1.518 0.74 2.31 0.86 ;
    END
  END VDD
  PIN VSS
    DIRECTION INOUT ;
    USE GROUND ;
    PORT
      LAYER metal0 ;
        RECT 0.99 -0.06 1.782 0.06 ;
        RECT -0.066 -0.06 0.726 0.06 ;
        RECT 1.518 -0.06 2.31 0.06 ;
        RECT 0.462 -0.06 1.254 0.06 ;
    END
  END VSS
  OBS
    LAYER metal0 ;
      RECT 1.168 0.26 1.538 0.3 ;
      RECT 1.467 0.26 2.132 0.3 ;
      RECT 0.411 0.26 1.2 0.3 ;
      RECT 0.112 0.26 0.482 0.3 ;
      RECT 1.63 0.5 2.198 0.54 ;
      RECT 1.102 0.5 1.67 0.54 ;
      RECT 2.158 0.66 2.198 0.7 ;
      RECT 0.046 0.5 0.614 0.54 ;
      RECT 2.158 0.1 2.198 0.14 ;
      RECT 0.574 0.5 1.142 0.54 ;
      RECT 1.366 0.66 1.406 0.7 ;
      RECT 0.046 0.66 0.086 0.7 ;
      RECT 0.31 0.1 0.35 0.14 ;
      RECT 1.102 0.1 1.142 0.14 ;
      RECT 1.63 0.1 1.67 0.14 ;
      RECT 0.31 0.66 0.35 0.7 ;
      RECT 1.102 0.66 1.142 0.7 ;
      RECT 0.046 0.1 0.086 0.14 ;
      RECT 1.894 0.66 1.934 0.7 ;
      RECT 1.894 0.1 1.934 0.14 ;
      RECT 1.366 0.1 1.406 0.14 ;
      RECT 0.574 0.66 0.614 0.7 ;
      RECT 0.574 0.1 0.614 0.14 ;
      RECT 0.838 0.66 0.878 0.7 ;
      RECT 1.63 0.66 1.67 0.7 ;
      RECT 0.838 0.1 0.878 0.14 ;
  END
END INV_X16

MACRO INV_X32
  CLASS CORE ;
  ORIGIN 0 0 ;
  FOREIGN INV_X32 0 0 ;
  SIZE 4.356 BY 0.8 ;
  PIN VDD
    DIRECTION INOUT ;
    USE POWER ;
    PORT
      LAYER metal0 ;
        RECT -0.238 0.853 4.25 0.973 ;
    END
  END VDD
  PIN VSS
    DIRECTION INOUT ;
    USE GROUND ;
    PORT
      LAYER metal0 ;
        RECT -0.238 0.053 4.25 0.173 ;
    END
  END VSS
  PIN A
    DIRECTION INOUT ;
    USE SIGNAL ;
    PORT
      LAYER metal1 ;
        RECT -0.008 0.36 0.058 0.426 ;
    END
  END A
  PIN ZN
    DIRECTION INOUT ;
    USE SIGNAL ;
    PORT
      LAYER metal1 ;
        RECT 4.085 0.2 4.151 0.826 ;
    END
  END ZN
  OBS
    LAYER metal1 SPACING 0 ;
      RECT -0.139 0.2 -0.073 0.826 ;
      RECT 0.125 0.2 0.191 0.826 ;
      RECT 0.389 0.2 0.455 0.826 ;
      RECT 0.653 0.2 0.719 0.826 ;
      RECT 0.917 0.2 0.983 0.826 ;
      RECT 1.181 0.2 1.247 0.826 ;
      RECT 1.445 0.2 1.511 0.826 ;
      RECT 1.709 0.2 1.775 0.826 ;
      RECT 1.973 0.2 2.039 0.826 ;
      RECT 2.237 0.2 2.303 0.826 ;
      RECT 2.501 0.2 2.567 0.826 ;
      RECT 2.765 0.2 2.831 0.826 ;
      RECT 3.029 0.2 3.095 0.826 ;
      RECT 3.293 0.2 3.359 0.826 ;
      RECT 3.557 0.2 3.623 0.826 ;
      RECT 3.821 0.2 3.887 0.826 ;
    LAYER metal0 SPACING 0 ;
      RECT -0.126 0.213 -0.086 0.253 ;
      RECT 0.138 0.213 0.178 0.253 ;
      RECT 0.402 0.213 0.442 0.253 ;
      RECT 0.666 0.213 0.706 0.253 ;
      RECT 0.93 0.213 0.97 0.253 ;
      RECT 1.194 0.213 1.234 0.253 ;
      RECT 1.458 0.213 1.498 0.253 ;
      RECT 1.722 0.213 1.762 0.253 ;
      RECT 1.986 0.213 2.026 0.253 ;
      RECT 2.25 0.213 2.29 0.253 ;
      RECT 2.514 0.213 2.554 0.253 ;
      RECT 2.778 0.213 2.818 0.253 ;
      RECT 3.042 0.213 3.082 0.253 ;
      RECT 3.306 0.213 3.346 0.253 ;
      RECT 3.57 0.213 3.61 0.253 ;
      RECT 3.834 0.213 3.874 0.253 ;
      RECT 4.098 0.213 4.138 0.253 ;
      RECT -0.06 0.373 4.072 0.413 ;
      RECT -0.126 0.613 4.138 0.653 ;
      RECT -0.126 0.773 -0.086 0.813 ;
      RECT 0.138 0.773 0.178 0.813 ;
      RECT 0.402 0.773 0.442 0.813 ;
      RECT 0.666 0.773 0.706 0.813 ;
      RECT 0.93 0.773 0.97 0.813 ;
      RECT 1.194 0.773 1.234 0.813 ;
      RECT 1.458 0.773 1.498 0.813 ;
      RECT 1.722 0.773 1.762 0.813 ;
      RECT 1.986 0.773 2.026 0.813 ;
      RECT 2.25 0.773 2.29 0.813 ;
      RECT 2.514 0.773 2.554 0.813 ;
      RECT 2.778 0.773 2.818 0.813 ;
      RECT 3.042 0.773 3.082 0.813 ;
      RECT 3.306 0.773 3.346 0.813 ;
      RECT 3.57 0.773 3.61 0.813 ;
      RECT 3.834 0.773 3.874 0.813 ;
      RECT 4.098 0.773 4.138 0.813 ;
  END
END INV_X32



MACRO MUX_X1
  CLASS CORE ;
  FOREIGN MUX_X1 0 0 ;
  SIZE 1.188 BY 0.8 ;
  ORIGIN 0.0 0.0 ;
  SYMMETRY X Y ;
  PIN A
    DIRECTION INPUT ;
    USE SIGNAL ;
    ANTENNAGATEAREA 0.008640 ;
    PORT
      LAYER metal1 ;
        RECT 0.429 0.487 0.495 0.553 ;
    END
  END A
  PIN B
    DIRECTION INPUT ;
    USE SIGNAL ;
    ANTENNAGATEAREA 0.008640 ;
    PORT
      LAYER metal1 ;
        RECT 0.693 0.247 0.759 0.313 ;
    END
  END B
  PIN S
    DIRECTION INPUT ;
    USE SIGNAL ;
    ANTENNAGATEAREA 0.017280 ;
    PORT
      LAYER metal1 ;
        RECT 0.429 0.327 0.495 0.473 ;
    END
  END S
  PIN Z
    DIRECTION OUTPUT ;
    USE SIGNAL ;
    ANTENNADIFFAREA 0.03888 ;
    PORT
      LAYER metal1 ;
        RECT 1.089 0.087 1.155 0.713 ;
    END
  END Z
  PIN VDD
    DIRECTION INOUT ;
    USE POWER ;
    PORT
      LAYER metal0 ;
        RECT -0.066 0.74 1.254 0.86 ;
    END
  END VDD
  PIN VSS
    DIRECTION INOUT ;
    USE GROUND ;
    PORT
      LAYER metal0 ;
        RECT -0.066 -0.06 1.254 0.06 ;
    END
  END VSS
  OBS
    LAYER metal1 ;
      RECT 0.165 0.087 0.231 0.713 ;
      RECT 0.561 0.247 0.627 0.473 ;
      RECT 0.297 0.087 0.363 0.713 ;
      RECT 0.825 0.087 0.891 0.713 ;
    LAYER metal0 ;
      RECT 0.574 0.42 0.812 0.46 ;
      RECT 0.178 0.26 0.614 0.3 ;
      RECT 0.31 0.58 1.076 0.62 ;
      RECT 0.178 0.66 0.218 0.7 ;
      RECT 0.178 0.1 0.218 0.14 ;
      RECT 0.31 0.66 0.35 0.7 ;
      RECT 0.838 0.66 0.878 0.7 ;
      RECT 0.31 0.1 0.35 0.14 ;
      RECT 0.838 0.1 0.878 0.14 ;
      RECT 0.442 0.5 0.548 0.54 ;
      RECT 0.64 0.26 0.746 0.3 ;
      RECT 0.442 0.34 0.812 0.38 ;
      RECT 0.112 0.42 0.482 0.46 ;
      RECT 1.102 0.1 1.142 0.14 ;
      RECT 1.102 0.66 1.142 0.7 ;
  END
END MUX_X1

MACRO MUX_X2
  CLASS CORE ;
  FOREIGN MUX_X2 0 0 ;
  SIZE 0.924 BY 1.6 ;
  ORIGIN 0.0 0.0 ;
  SYMMETRY X Y ;
  PIN A
    DIRECTION INPUT ;
    USE SIGNAL ;
    ANTENNAGATEAREA 0.008640 ;
    PORT
      LAYER metal1 ;
        RECT 0.561 1.047 0.627 1.113 ;
    END
  END A
  PIN B
    DIRECTION INPUT ;
    USE SIGNAL ;
    ANTENNAGATEAREA 0.012960 ;
    PORT
      LAYER metal1 ;
        RECT 0.561 0.967 0.627 1.033 ;
    END
  END B
  PIN S
    DIRECTION INPUT ;
    USE SIGNAL ;
    ANTENNAGATEAREA 0.021600 ;
    PORT
      LAYER metal1 ;
        RECT 0.429 0.647 0.495 1.273 ;
    END
  END S
  PIN Z
    DIRECTION OUTPUT ;
    USE SIGNAL ;
    ANTENNADIFFAREA 0.03888 ;
    PORT
      LAYER metal1 ;
        RECT 0.165 0.087 0.231 0.713 ;
    END
  END Z
  PIN VDD
    DIRECTION INOUT ;
    USE POWER ;
    PORT
      LAYER metal0 ;
        RECT -0.066 1.54 0.99 1.66 ;
        RECT -0.066 -0.06 0.99 0.06 ;
    END
  END VDD
  PIN VSS
    DIRECTION INOUT ;
    USE GROUND ;
    PORT
      LAYER metal0 ;
        RECT -0.066 0.74 0.99 0.86 ;
    END
  END VSS
  OBS
    LAYER metal1 ;
      RECT 0.561 0.087 0.627 0.953 ;
      RECT 0.297 0.567 0.363 1.513 ;
      RECT 0.693 0.887 0.759 1.193 ;
      RECT 0.825 1.127 0.891 1.513 ;
    LAYER metal0 ;
      RECT 0.508 0.9 0.614 0.94 ;
      RECT 0.31 1.14 0.878 1.18 ;
      RECT 0.178 0.9 0.35 0.94 ;
      RECT 0.112 0.58 0.35 0.62 ;
      RECT 0.442 1.46 0.746 1.5 ;
      RECT 0.574 0.66 0.614 0.7 ;
      RECT 0.574 0.1 0.614 0.14 ;
      RECT 0.31 1.46 0.35 1.5 ;
      RECT 0.838 1.46 0.878 1.5 ;
      RECT 0.706 0.9 0.746 0.94 ;
      RECT 0.574 1.06 0.68 1.1 ;
      RECT 0.376 0.98 0.812 1.02 ;
      RECT 0.244 1.22 0.482 1.26 ;
      RECT 0.442 0.66 0.548 0.7 ;
      RECT 0.178 0.66 0.218 0.7 ;
      RECT 0.178 0.1 0.218 0.14 ;
  END
END MUX_X2

MACRO NAND2_X1
  CLASS CORE ;
  FOREIGN NAND2_X1 0 0 ;
  SIZE 0.396 BY 0.8 ;
  ORIGIN 0.0 0.0 ;
  SYMMETRY X Y ;
  PIN A1
    DIRECTION INPUT ;
    USE SIGNAL ;
    ANTENNAGATEAREA 0.008640 ;
    PORT
      LAYER metal1 ;
        RECT 0.165 0.167 0.231 0.233 ;
    END
  END A1
  PIN A2
    DIRECTION INPUT ;
    USE SIGNAL ;
    ANTENNAGATEAREA 0.008640 ;
    PORT
      LAYER metal1 ;
        RECT 0.165 0.087 0.231 0.153 ;
    END
  END A2
  PIN ZN
    DIRECTION OUTPUT ;
    USE SIGNAL ;
    ANTENNADIFFAREA 0.03888 ;
    PORT
      LAYER metal1 ;
        RECT 0.033 0.087 0.099 0.713 ;
    END
  END ZN
  PIN VDD
    DIRECTION INOUT ;
    USE POWER ;
    PORT
      LAYER metal0 ;
        RECT -0.066 0.74 0.462 0.86 ;
    END
  END VDD
  PIN VSS
    DIRECTION INOUT ;
    USE GROUND ;
    PORT
      LAYER metal0 ;
        RECT -0.066 -0.06 0.462 0.06 ;
    END
  END VSS
  OBS
    LAYER metal0 ;
      RECT 0.112 0.18 0.218 0.22 ;
      RECT 0.178 0.1 0.284 0.14 ;
      RECT 0.046 0.66 0.218 0.7 ;
      RECT 0.046 0.1 0.086 0.14 ;
  END
END NAND2_X1

MACRO NAND2_X2
  CLASS CORE ;
  FOREIGN NAND2_X2 0 0 ;
  SIZE 0.66 BY 0.8 ;
  ORIGIN 0.0 0.0 ;
  SYMMETRY X Y ;
  PIN A1
    DIRECTION INPUT ;
    USE SIGNAL ;
    ANTENNAGATEAREA 0.012960 ;
    PORT
      LAYER metal1 ;
        RECT 0.429 0.567 0.495 0.633 ;
    END
  END A1
  PIN A2
    DIRECTION INPUT ;
    USE SIGNAL ;
    ANTENNAGATEAREA 0.017280 ;
    PORT
      LAYER metal1 ;
        RECT 0.429 0.327 0.495 0.473 ;
    END
  END A2
  PIN ZN
    DIRECTION OUTPUT ;
    USE SIGNAL ;
    ANTENNADIFFAREA 0.05832 ;
    PORT
      LAYER metal1 ;
        RECT 0.297 0.087 0.363 0.713 ;
    END
  END ZN
  PIN VDD
    DIRECTION INOUT ;
    USE POWER ;
    PORT
      LAYER metal0 ;
        RECT -0.066 0.74 0.726 0.86 ;
    END
  END VDD
  PIN VSS
    DIRECTION INOUT ;
    USE GROUND ;
    PORT
      LAYER metal0 ;
        RECT -0.066 -0.06 0.726 0.06 ;
    END
  END VSS
  OBS
    LAYER metal0 ;
      RECT 0.244 0.34 0.416 0.38 ;
      RECT 0.244 0.58 0.548 0.62 ;
      RECT 0.442 0.34 0.548 0.38 ;
      RECT 0.112 0.42 0.482 0.46 ;
      RECT 0.31 0.1 0.35 0.14 ;
      RECT 0.178 0.66 0.482 0.7 ;
  END
END NAND2_X2

MACRO NAND2_X4
  CLASS CORE ;
  FOREIGN NAND2_X4 0 0 ;
  SIZE 1.188 BY 0.8 ;
  ORIGIN 0.0 0.0 ;
  SYMMETRY X Y ;
  PIN A1
    DIRECTION INPUT ;
    USE SIGNAL ;
    ANTENNAGATEAREA 0.034560 ;
    PORT
      LAYER metal1 ;
        RECT 0.297 0.567 0.363 0.633 ;
    END
  END A1
  PIN A2
    DIRECTION INPUT ;
    USE SIGNAL ;
    ANTENNAGATEAREA 0.034560 ;
    PORT
      LAYER metal1 ;
        RECT 0.825 0.487 0.891 0.553 ;
    END
  END A2
  PIN ZN
    DIRECTION OUTPUT ;
    USE SIGNAL ;
    ANTENNADIFFAREA 0.11664 ;
    PORT
      LAYER metal1 ;
        RECT 0.561 0.567 0.627 0.713 ;
        RECT 0.693 0.087 0.759 0.713 ;
        RECT 0.957 0.087 1.023 0.713 ;
    END
  END ZN
  PIN VDD
    DIRECTION INOUT ;
    USE POWER ;
    PORT
      LAYER metal0 ;
        RECT -0.066 0.74 1.254 0.86 ;
    END
  END VDD
  PIN VSS
    DIRECTION INOUT ;
    USE GROUND ;
    PORT
      LAYER metal0 ;
        RECT -0.066 -0.06 1.254 0.06 ;
    END
  END VSS
  OBS
    LAYER metal1 ;
      RECT 0.429 0.087 0.495 0.233 ;
      RECT 0.561 0.087 0.627 0.233 ;
      RECT 0.825 0.087 0.891 0.233 ;
      RECT 1.089 0.087 1.155 0.233 ;
    LAYER metal0 ;
      RECT 0.442 0.18 1.142 0.22 ;
      RECT 0.046 0.1 0.482 0.14 ;
      RECT 0.574 0.1 0.614 0.14 ;
      RECT 0.838 0.1 0.878 0.14 ;
      RECT 1.102 0.1 1.142 0.14 ;
      RECT 0.112 0.58 0.548 0.62 ;
      RECT 0.64 0.5 1.076 0.54 ;
      RECT 0.178 0.66 0.614 0.7 ;
      RECT 0.574 0.58 1.01 0.62 ;
      RECT 0.97 0.66 1.01 0.7 ;
      RECT 0.97 0.1 1.01 0.14 ;
      RECT 0.706 0.66 0.746 0.7 ;
      RECT 0.706 0.1 0.746 0.14 ;
  END
END NAND2_X4

MACRO NAND3_X1
  CLASS CORE ;
  FOREIGN NAND3_X1 0 0 ;
  SIZE 0.528 BY 0.8 ;
  ORIGIN 0.0 0.0 ;
  SYMMETRY X Y ;
  PIN A1
    DIRECTION INPUT ;
    USE SIGNAL ;
    ANTENNAGATEAREA 0.008640 ;
    PORT
      LAYER metal1 ;
        RECT 0.297 0.087 0.363 0.153 ;
    END
  END A1
  PIN A2
    DIRECTION INPUT ;
    USE SIGNAL ;
    ANTENNAGATEAREA 0.008640 ;
    PORT
      LAYER metal1 ;
        RECT 0.165 0.567 0.231 0.633 ;
    END
  END A2
  PIN A3
    DIRECTION INPUT ;
    USE SIGNAL ;
    ANTENNAGATEAREA 0.008640 ;
    PORT
      LAYER metal1 ;
        RECT 0.033 0.567 0.099 0.633 ;
    END
  END A3
  PIN ZN
    DIRECTION OUTPUT ;
    USE SIGNAL ;
    ANTENNADIFFAREA 0.05832 ;
    PORT
      LAYER metal1 ;
        RECT 0.429 0.087 0.495 0.713 ;
    END
  END ZN
  PIN VDD
    DIRECTION INOUT ;
    USE POWER ;
    PORT
      LAYER metal0 ;
        RECT -0.066 0.74 0.594 0.86 ;
    END
  END VDD
  PIN VSS
    DIRECTION INOUT ;
    USE GROUND ;
    PORT
      LAYER metal0 ;
        RECT -0.066 -0.06 0.594 0.06 ;
    END
  END VSS
  OBS
    LAYER metal0 ;
      RECT 0.31 0.1 0.416 0.14 ;
      RECT 0.178 0.58 0.284 0.62 ;
      RECT 0.046 0.58 0.152 0.62 ;
      RECT 0.046 0.66 0.482 0.7 ;
      RECT 0.442 0.1 0.482 0.14 ;
  END
END NAND3_X1

MACRO NAND4_X1
  CLASS CORE ;
  FOREIGN NAND4_X1 0 0 ;
  SIZE 0.792 BY 0.8 ;
  ORIGIN 0.0 0.0 ;
  SYMMETRY X Y ;
  PIN A1
    DIRECTION INPUT ;
    USE SIGNAL ;
    ANTENNAGATEAREA 0.008640 ;
    PORT
      LAYER metal1 ;
        RECT 0.165 0.327 0.231 0.393 ;
    END
  END A1
  PIN A2
    DIRECTION INPUT ;
    USE SIGNAL ;
    ANTENNAGATEAREA 0.008640 ;
    PORT
      LAYER metal1 ;
        RECT 0.165 0.487 0.231 0.553 ;
    END
  END A2
  PIN A3
    DIRECTION INPUT ;
    USE SIGNAL ;
    ANTENNAGATEAREA 0.008640 ;
    PORT
      LAYER metal1 ;
        RECT 0.297 0.567 0.363 0.633 ;
    END
  END A3
  PIN A4
    DIRECTION INPUT ;
    USE SIGNAL ;
    ANTENNAGATEAREA 0.008640 ;
    PORT
      LAYER metal1 ;
        RECT 0.561 0.407 0.627 0.473 ;
    END
  END A4
  PIN ZN
    DIRECTION OUTPUT ;
    USE SIGNAL ;
    ANTENNADIFFAREA 0.07776 ;
    PORT
      LAYER metal1 ;
        RECT 0.033 0.087 0.099 0.713 ;
    END
  END ZN
  PIN VDD
    DIRECTION INOUT ;
    USE POWER ;
    PORT
      LAYER metal0 ;
        RECT -0.066 0.74 0.858 0.86 ;
    END
  END VDD
  PIN VSS
    DIRECTION INOUT ;
    USE GROUND ;
    PORT
      LAYER metal0 ;
        RECT -0.066 -0.06 0.858 0.06 ;
    END
  END VSS
  OBS
    LAYER metal0 ;
      RECT 0.442 0.1 0.614 0.14 ;
      RECT 0.112 0.34 0.218 0.38 ;
      RECT 0.178 0.5 0.284 0.54 ;
      RECT 0.31 0.58 0.416 0.62 ;
      RECT 0.574 0.42 0.68 0.46 ;
      RECT 0.046 0.1 0.086 0.14 ;
      RECT 0.046 0.66 0.746 0.7 ;
  END
END NAND4_X1

MACRO NOR2_X1
  CLASS CORE ;
  FOREIGN NOR2_X1 0 0 ;
  SIZE 0.396 BY 0.8 ;
  ORIGIN 0.0 0.0 ;
  SYMMETRY X Y ;
  PIN A1
    DIRECTION INPUT ;
    USE SIGNAL ;
    ANTENNAGATEAREA 0.008640 ;
    PORT
      LAYER metal1 ;
        RECT 0.165 0.407 0.231 0.473 ;
    END
  END A1
  PIN A2
    DIRECTION INPUT ;
    USE SIGNAL ;
    ANTENNAGATEAREA 0.008640 ;
    PORT
      LAYER metal1 ;
        RECT 0.033 0.647 0.099 0.713 ;
    END
  END A2
  PIN ZN
    DIRECTION OUTPUT ;
    USE SIGNAL ;
    ANTENNADIFFAREA 0.03888 ;
    PORT
      LAYER metal1 ;
        RECT 0.297 0.087 0.363 0.713 ;
    END
  END ZN
  PIN VDD
    DIRECTION INOUT ;
    USE POWER ;
    PORT
      LAYER metal0 ;
        RECT -0.066 0.74 0.462 0.86 ;
    END
  END VDD
  PIN VSS
    DIRECTION INOUT ;
    USE GROUND ;
    PORT
      LAYER metal0 ;
        RECT -0.066 -0.06 0.462 0.06 ;
    END
  END VSS
  OBS
    LAYER metal0 ;
      RECT 0.178 0.42 0.284 0.46 ;
      RECT 0.046 0.66 0.152 0.7 ;
      RECT 0.31 0.66 0.35 0.7 ;
      RECT 0.178 0.1 0.35 0.14 ;
  END
END NOR2_X1

MACRO NOR2_X2
  CLASS CORE ;
  FOREIGN NOR2_X2 0 0 ;
  SIZE 0.66 BY 0.8 ;
  ORIGIN 0.0 0.0 ;
  SYMMETRY X Y ;
  PIN A1
    DIRECTION INPUT ;
    USE SIGNAL ;
    ANTENNAGATEAREA 0.017280 ;
    PORT
      LAYER metal1 ;
        RECT 0.297 0.247 0.363 0.473 ;
    END
  END A1
  PIN A2
    DIRECTION INPUT ;
    USE SIGNAL ;
    ANTENNAGATEAREA 0.017280 ;
    PORT
      LAYER metal1 ;
        RECT 0.165 0.327 0.231 0.473 ;
    END
  END A2
  PIN ZN
    DIRECTION OUTPUT ;
    USE SIGNAL ;
    ANTENNADIFFAREA 0.05832 ;
    PORT
      LAYER metal1 ;
        RECT 0.297 0.087 0.363 0.233 ;
        RECT 0.429 0.087 0.495 0.713 ;
    END
  END ZN
  PIN VDD
    DIRECTION INOUT ;
    USE POWER ;
    PORT
      LAYER metal0 ;
        RECT -0.066 0.74 0.726 0.86 ;
    END
  END VDD
  PIN VSS
    DIRECTION INOUT ;
    USE GROUND ;
    PORT
      LAYER metal0 ;
        RECT -0.066 -0.06 0.726 0.06 ;
    END
  END VSS
  OBS
    LAYER metal0 ;
      RECT 0.112 0.26 0.35 0.3 ;
      RECT 0.244 0.42 0.416 0.46 ;
      RECT 0.178 0.34 0.548 0.38 ;
      RECT 0.112 0.42 0.218 0.46 ;
      RECT 0.178 0.1 0.35 0.14 ;
      RECT 0.31 0.18 0.482 0.22 ;
      RECT 0.31 0.66 0.482 0.7 ;
      RECT 0.442 0.1 0.482 0.14 ;
  END
END NOR2_X2

MACRO NOR2_X4
  CLASS CORE ;
  FOREIGN NOR2_X4 0 0 ;
  SIZE 1.188 BY 0.8 ;
  ORIGIN 0.0 0.0 ;
  SYMMETRY X Y ;
  PIN A1
    DIRECTION INPUT ;
    USE SIGNAL ;
    ANTENNAGATEAREA 0.034560 ;
    PORT
      LAYER metal1 ;
        RECT 0.429 0.327 0.495 0.393 ;
    END
  END A1
  PIN A2
    DIRECTION INPUT ;
    USE SIGNAL ;
    ANTENNAGATEAREA 0.034560 ;
    PORT
      LAYER metal1 ;
        RECT 0.825 0.327 0.891 0.393 ;
    END
  END A2
  PIN ZN
    DIRECTION OUTPUT ;
    USE SIGNAL ;
    ANTENNADIFFAREA 0.13608 ;
    PORT
      LAYER metal1 ;
        RECT 0.693 0.087 0.759 0.713 ;
        RECT 0.957 0.087 1.023 0.713 ;
    END
  END ZN
  PIN VDD
    DIRECTION INOUT ;
    USE POWER ;
    PORT
      LAYER metal0 ;
        RECT -0.066 0.74 1.254 0.86 ;
    END
  END VDD
  PIN VSS
    DIRECTION INOUT ;
    USE GROUND ;
    PORT
      LAYER metal0 ;
        RECT -0.066 -0.06 1.254 0.06 ;
    END
  END VSS
  OBS
    LAYER metal1 ;
      RECT 0.429 0.567 0.495 0.713 ;
      RECT 0.561 0.567 0.627 0.713 ;
      RECT 0.825 0.567 0.891 0.713 ;
      RECT 1.089 0.567 1.155 0.713 ;
    LAYER metal0 ;
      RECT 0.046 0.66 0.482 0.7 ;
      RECT 0.442 0.58 1.142 0.62 ;
      RECT 0.574 0.66 0.614 0.7 ;
      RECT 0.838 0.66 0.878 0.7 ;
      RECT 1.102 0.66 1.142 0.7 ;
      RECT 0.112 0.34 0.548 0.38 ;
      RECT 0.64 0.34 1.076 0.38 ;
      RECT 0.046 0.1 1.142 0.14 ;
      RECT 0.706 0.66 0.746 0.7 ;
      RECT 0.97 0.66 1.01 0.7 ;
  END
END NOR2_X4

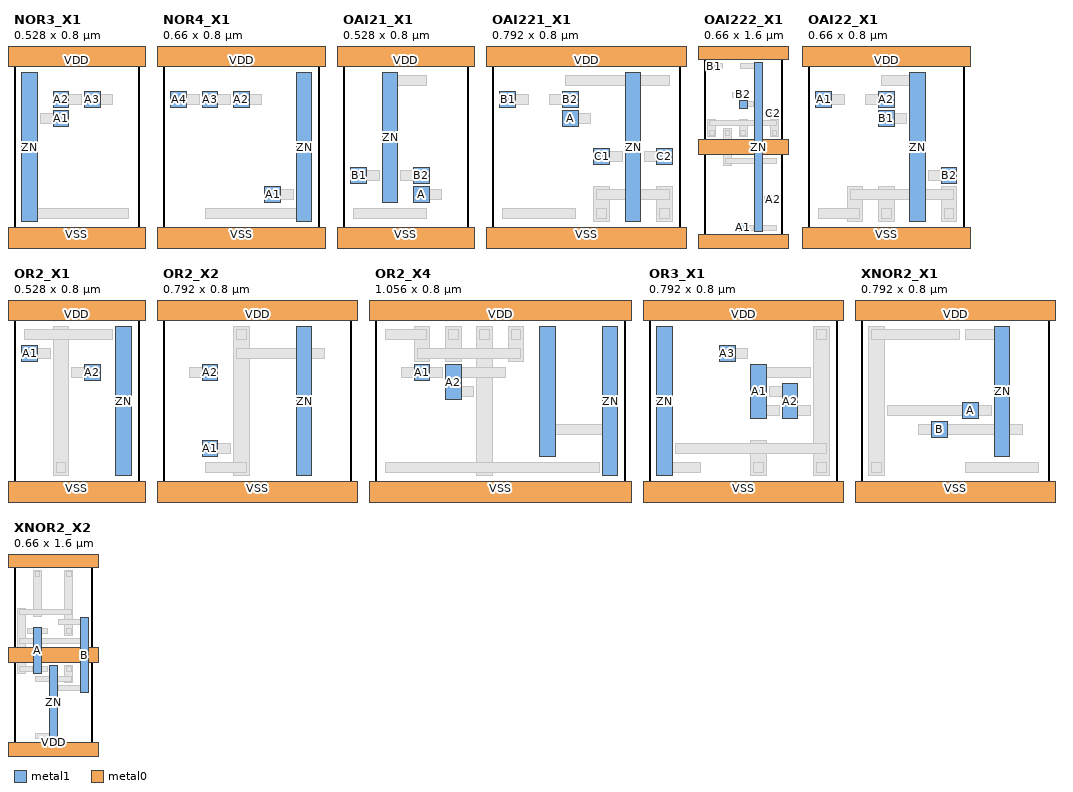
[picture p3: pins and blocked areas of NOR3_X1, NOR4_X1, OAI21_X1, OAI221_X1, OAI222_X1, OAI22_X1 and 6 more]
MACRO NOR3_X1
  CLASS CORE ;
  FOREIGN NOR3_X1 0 0 ;
  SIZE 0.528 BY 0.8 ;
  ORIGIN 0.0 0.0 ;
  SYMMETRY X Y ;
  PIN A1
    DIRECTION INPUT ;
    USE SIGNAL ;
    ANTENNAGATEAREA 0.008640 ;
    PORT
      LAYER metal1 ;
        RECT 0.165 0.487 0.231 0.553 ;
    END
  END A1
  PIN A2
    DIRECTION INPUT ;
    USE SIGNAL ;
    ANTENNAGATEAREA 0.008640 ;
    PORT
      LAYER metal1 ;
        RECT 0.165 0.567 0.231 0.633 ;
    END
  END A2
  PIN A3
    DIRECTION INPUT ;
    USE SIGNAL ;
    ANTENNAGATEAREA 0.008640 ;
    PORT
      LAYER metal1 ;
        RECT 0.297 0.567 0.363 0.633 ;
    END
  END A3
  PIN ZN
    DIRECTION OUTPUT ;
    USE SIGNAL ;
    ANTENNADIFFAREA 0.05832 ;
    PORT
      LAYER metal1 ;
        RECT 0.033 0.087 0.099 0.713 ;
    END
  END ZN
  PIN VDD
    DIRECTION INOUT ;
    USE POWER ;
    PORT
      LAYER metal0 ;
        RECT -0.066 0.74 0.594 0.86 ;
    END
  END VDD
  PIN VSS
    DIRECTION INOUT ;
    USE GROUND ;
    PORT
      LAYER metal0 ;
        RECT -0.066 -0.06 0.594 0.06 ;
    END
  END VSS
  OBS
    LAYER metal0 ;
      RECT 0.112 0.5 0.218 0.54 ;
      RECT 0.178 0.58 0.284 0.62 ;
      RECT 0.31 0.58 0.416 0.62 ;
      RECT 0.046 0.66 0.086 0.7 ;
      RECT 0.046 0.1 0.482 0.14 ;
  END
END NOR3_X1

MACRO NOR4_X1
  CLASS CORE ;
  FOREIGN NOR4_X1 0 0 ;
  SIZE 0.66 BY 0.8 ;
  ORIGIN 0.0 0.0 ;
  SYMMETRY X Y ;
  PIN A1
    DIRECTION INPUT ;
    USE SIGNAL ;
    ANTENNAGATEAREA 0.008640 ;
    PORT
      LAYER metal1 ;
        RECT 0.429 0.167 0.495 0.233 ;
    END
  END A1
  PIN A2
    DIRECTION INPUT ;
    USE SIGNAL ;
    ANTENNAGATEAREA 0.008640 ;
    PORT
      LAYER metal1 ;
        RECT 0.297 0.567 0.363 0.633 ;
    END
  END A2
  PIN A3
    DIRECTION INPUT ;
    USE SIGNAL ;
    ANTENNAGATEAREA 0.008640 ;
    PORT
      LAYER metal1 ;
        RECT 0.165 0.567 0.231 0.633 ;
    END
  END A3
  PIN A4
    DIRECTION INPUT ;
    USE SIGNAL ;
    ANTENNAGATEAREA 0.008640 ;
    PORT
      LAYER metal1 ;
        RECT 0.033 0.567 0.099 0.633 ;
    END
  END A4
  PIN ZN
    DIRECTION OUTPUT ;
    USE SIGNAL ;
    ANTENNADIFFAREA 0.05832 ;
    PORT
      LAYER metal1 ;
        RECT 0.561 0.087 0.627 0.713 ;
    END
  END ZN
  PIN VDD
    DIRECTION INOUT ;
    USE POWER ;
    PORT
      LAYER metal0 ;
        RECT -0.066 0.74 0.726 0.86 ;
    END
  END VDD
  PIN VSS
    DIRECTION INOUT ;
    USE GROUND ;
    PORT
      LAYER metal0 ;
        RECT -0.066 -0.06 0.726 0.06 ;
    END
  END VSS
  OBS
    LAYER metal0 ;
      RECT 0.442 0.18 0.548 0.22 ;
      RECT 0.31 0.58 0.416 0.62 ;
      RECT 0.178 0.58 0.284 0.62 ;
      RECT 0.046 0.58 0.152 0.62 ;
      RECT 0.178 0.1 0.614 0.14 ;
      RECT 0.574 0.66 0.614 0.7 ;
  END
END NOR4_X1

MACRO OAI21_X1
  CLASS CORE ;
  FOREIGN OAI21_X1 0 0 ;
  SIZE 0.528 BY 0.8 ;
  ORIGIN 0.0 0.0 ;
  SYMMETRY X Y ;
  PIN A
    DIRECTION INPUT ;
    USE SIGNAL ;
    ANTENNAGATEAREA 0.008640 ;
    PORT
      LAYER metal1 ;
        RECT 0.297 0.167 0.363 0.233 ;
    END
  END A
  PIN B1
    DIRECTION INPUT ;
    USE SIGNAL ;
    ANTENNAGATEAREA 0.008640 ;
    PORT
      LAYER metal1 ;
        RECT 0.033 0.247 0.099 0.313 ;
    END
  END B1
  PIN B2
    DIRECTION INPUT ;
    USE SIGNAL ;
    ANTENNAGATEAREA 0.008640 ;
    PORT
      LAYER metal1 ;
        RECT 0.297 0.247 0.363 0.313 ;
    END
  END B2
  PIN ZN
    DIRECTION OUTPUT ;
    USE SIGNAL ;
    ANTENNADIFFAREA 0.03888 ;
    PORT
      LAYER metal1 ;
        RECT 0.165 0.167 0.231 0.713 ;
    END
  END ZN
  PIN VDD
    DIRECTION INOUT ;
    USE POWER ;
    PORT
      LAYER metal0 ;
        RECT -0.066 0.74 0.594 0.86 ;
    END
  END VDD
  PIN VSS
    DIRECTION INOUT ;
    USE GROUND ;
    PORT
      LAYER metal0 ;
        RECT -0.066 -0.06 0.594 0.06 ;
    END
  END VSS
  OBS
    LAYER metal0 ;
      RECT 0.046 0.1 0.35 0.14 ;
      RECT 0.31 0.18 0.416 0.22 ;
      RECT 0.046 0.26 0.152 0.3 ;
      RECT 0.244 0.26 0.35 0.3 ;
      RECT 0.178 0.66 0.35 0.7 ;
      RECT 0.178 0.18 0.218 0.22 ;
  END
END OAI21_X1

MACRO OAI221_X1
  CLASS CORE ;
  FOREIGN OAI221_X1 0 0 ;
  SIZE 0.792 BY 0.8 ;
  ORIGIN 0.0 0.0 ;
  SYMMETRY X Y ;
  PIN A
    DIRECTION INPUT ;
    USE SIGNAL ;
    ANTENNAGATEAREA 0.008640 ;
    PORT
      LAYER metal1 ;
        RECT 0.297 0.487 0.363 0.553 ;
    END
  END A
  PIN B1
    DIRECTION INPUT ;
    USE SIGNAL ;
    ANTENNAGATEAREA 0.008640 ;
    PORT
      LAYER metal1 ;
        RECT 0.033 0.567 0.099 0.633 ;
    END
  END B1
  PIN B2
    DIRECTION INPUT ;
    USE SIGNAL ;
    ANTENNAGATEAREA 0.008640 ;
    PORT
      LAYER metal1 ;
        RECT 0.297 0.567 0.363 0.633 ;
    END
  END B2
  PIN C1
    DIRECTION INPUT ;
    USE SIGNAL ;
    ANTENNAGATEAREA 0.008640 ;
    PORT
      LAYER metal1 ;
        RECT 0.429 0.327 0.495 0.393 ;
    END
  END C1
  PIN C2
    DIRECTION INPUT ;
    USE SIGNAL ;
    ANTENNAGATEAREA 0.008640 ;
    PORT
      LAYER metal1 ;
        RECT 0.693 0.327 0.759 0.393 ;
    END
  END C2
  PIN ZN
    DIRECTION OUTPUT ;
    USE SIGNAL ;
    ANTENNADIFFAREA 0.05832 ;
    PORT
      LAYER metal1 ;
        RECT 0.561 0.087 0.627 0.713 ;
    END
  END ZN
  PIN VDD
    DIRECTION INOUT ;
    USE POWER ;
    PORT
      LAYER metal0 ;
        RECT -0.066 0.74 0.858 0.86 ;
    END
  END VDD
  PIN VSS
    DIRECTION INOUT ;
    USE GROUND ;
    PORT
      LAYER metal0 ;
        RECT -0.066 -0.06 0.858 0.06 ;
    END
  END VSS
  OBS
    LAYER metal1 ;
      RECT 0.429 0.087 0.495 0.233 ;
      RECT 0.693 0.087 0.759 0.233 ;
    LAYER metal0 ;
      RECT 0.046 0.1 0.35 0.14 ;
      RECT 0.442 0.18 0.746 0.22 ;
      RECT 0.442 0.1 0.482 0.14 ;
      RECT 0.706 0.1 0.746 0.14 ;
      RECT 0.31 0.5 0.416 0.54 ;
      RECT 0.046 0.58 0.152 0.62 ;
      RECT 0.244 0.58 0.35 0.62 ;
      RECT 0.442 0.34 0.548 0.38 ;
      RECT 0.64 0.34 0.746 0.38 ;
      RECT 0.31 0.66 0.746 0.7 ;
      RECT 0.574 0.1 0.614 0.14 ;
  END
END OAI221_X1

MACRO OAI222_X1
  CLASS CORE ;
  FOREIGN OAI222_X1 0 0 ;
  SIZE 0.66 BY 1.6 ;
  ORIGIN 0.0 0.0 ;
  SYMMETRY X Y ;
  PIN A1
    DIRECTION INPUT ;
    USE SIGNAL ;
    ANTENNAGATEAREA 0.008640 ;
    PORT
      LAYER metal1 ;
        RECT 0.297 0.087 0.363 0.153 ;
    END
  END A1
  PIN A2
    DIRECTION INPUT ;
    USE SIGNAL ;
    ANTENNAGATEAREA 0.008640 ;
    PORT
      LAYER metal1 ;
        RECT 0.561 0.327 0.627 0.393 ;
    END
  END A2
  PIN B1
    DIRECTION INPUT ;
    USE SIGNAL ;
    ANTENNAGATEAREA 0.008640 ;
    PORT
      LAYER metal1 ;
        RECT 0.033 1.447 0.099 1.513 ;
    END
  END B1
  PIN B2
    DIRECTION INPUT ;
    USE SIGNAL ;
    ANTENNAGATEAREA 0.008640 ;
    PORT
      LAYER metal1 ;
        RECT 0.297 1.207 0.363 1.273 ;
    END
  END B2
  PIN C1
    DIRECTION INPUT ;
    USE SIGNAL ;
    ANTENNAGATEAREA 0.008640 ;
    PORT
      LAYER metal1 ;
        RECT 0.297 1.127 0.363 1.193 ;
    END
  END C1
  PIN C2
    DIRECTION INPUT ;
    USE SIGNAL ;
    ANTENNAGATEAREA 0.008640 ;
    PORT
      LAYER metal1 ;
        RECT 0.561 1.047 0.627 1.113 ;
    END
  END C2
  PIN ZN
    DIRECTION OUTPUT ;
    USE SIGNAL ;
    ANTENNADIFFAREA 0.05832 ;
    PORT
      LAYER metal1 ;
        RECT 0.429 0.087 0.495 1.513 ;
    END
  END ZN
  PIN VDD
    DIRECTION INOUT ;
    USE POWER ;
    PORT
      LAYER metal0 ;
        RECT -0.066 -0.06 0.726 0.06 ;
        RECT -0.066 1.54 0.726 1.66 ;
    END
  END VDD
  PIN VSS
    DIRECTION INOUT ;
    USE GROUND ;
    PORT
      LAYER metal0 ;
        RECT -0.066 0.74 0.726 0.86 ;
    END
  END VSS
  OBS
    LAYER metal1 ;
      RECT 0.561 0.887 0.627 1.033 ;
      RECT 0.297 0.887 0.363 1.033 ;
      RECT 0.033 0.887 0.099 1.033 ;
      RECT 0.165 0.647 0.231 0.953 ;
    LAYER metal0 ;
      RECT 0.574 0.9 0.614 0.94 ;
      RECT 0.31 0.9 0.35 0.94 ;
      RECT 0.046 0.9 0.086 0.94 ;
      RECT 0.178 0.9 0.218 0.94 ;
      RECT 0.046 0.98 0.614 1.02 ;
      RECT 0.178 0.66 0.614 0.7 ;
      RECT 0.31 0.1 0.416 0.14 ;
      RECT 0.508 0.34 0.614 0.38 ;
      RECT 0.046 1.46 0.152 1.5 ;
      RECT 0.244 1.22 0.35 1.26 ;
      RECT 0.31 1.14 0.416 1.18 ;
      RECT 0.508 1.06 0.614 1.1 ;
      RECT 0.442 0.1 0.614 0.14 ;
      RECT 0.442 0.58 0.482 0.62 ;
      RECT 0.31 1.46 0.482 1.5 ;
  END
END OAI222_X1

MACRO OAI22_X1
  CLASS CORE ;
  FOREIGN OAI22_X1 0 0 ;
  SIZE 0.66 BY 0.8 ;
  ORIGIN 0.0 0.0 ;
  SYMMETRY X Y ;
  PIN A1
    DIRECTION INPUT ;
    USE SIGNAL ;
    ANTENNAGATEAREA 0.008640 ;
    PORT
      LAYER metal1 ;
        RECT 0.033 0.567 0.099 0.633 ;
    END
  END A1
  PIN A2
    DIRECTION INPUT ;
    USE SIGNAL ;
    ANTENNAGATEAREA 0.008640 ;
    PORT
      LAYER metal1 ;
        RECT 0.297 0.567 0.363 0.633 ;
    END
  END A2
  PIN B1
    DIRECTION INPUT ;
    USE SIGNAL ;
    ANTENNAGATEAREA 0.008640 ;
    PORT
      LAYER metal1 ;
        RECT 0.297 0.487 0.363 0.553 ;
    END
  END B1
  PIN B2
    DIRECTION INPUT ;
    USE SIGNAL ;
    ANTENNAGATEAREA 0.008640 ;
    PORT
      LAYER metal1 ;
        RECT 0.561 0.247 0.627 0.313 ;
    END
  END B2
  PIN ZN
    DIRECTION OUTPUT ;
    USE SIGNAL ;
    ANTENNADIFFAREA 0.03888 ;
    PORT
      LAYER metal1 ;
        RECT 0.429 0.087 0.495 0.713 ;
    END
  END ZN
  PIN VDD
    DIRECTION INOUT ;
    USE POWER ;
    PORT
      LAYER metal0 ;
        RECT -0.066 0.74 0.726 0.86 ;
    END
  END VDD
  PIN VSS
    DIRECTION INOUT ;
    USE GROUND ;
    PORT
      LAYER metal0 ;
        RECT -0.066 -0.06 0.726 0.06 ;
    END
  END VSS
  OBS
    LAYER metal1 ;
      RECT 0.165 0.087 0.231 0.233 ;
      RECT 0.297 0.087 0.363 0.233 ;
      RECT 0.561 0.087 0.627 0.233 ;
    LAYER metal0 ;
      RECT 0.178 0.18 0.614 0.22 ;
      RECT 0.046 0.1 0.218 0.14 ;
      RECT 0.31 0.1 0.35 0.14 ;
      RECT 0.574 0.1 0.614 0.14 ;
      RECT 0.046 0.58 0.152 0.62 ;
      RECT 0.244 0.58 0.35 0.62 ;
      RECT 0.31 0.5 0.416 0.54 ;
      RECT 0.508 0.26 0.614 0.3 ;
      RECT 0.31 0.66 0.482 0.7 ;
      RECT 0.442 0.1 0.482 0.14 ;
  END
END OAI22_X1

MACRO OR2_X1
  CLASS CORE ;
  FOREIGN OR2_X1 0 0 ;
  SIZE 0.528 BY 0.8 ;
  ORIGIN 0.0 0.0 ;
  SYMMETRY X Y ;
  PIN A1
    DIRECTION INPUT ;
    USE SIGNAL ;
    ANTENNAGATEAREA 0.008640 ;
    PORT
      LAYER metal1 ;
        RECT 0.033 0.567 0.099 0.633 ;
    END
  END A1
  PIN A2
    DIRECTION INPUT ;
    USE SIGNAL ;
    ANTENNAGATEAREA 0.008640 ;
    PORT
      LAYER metal1 ;
        RECT 0.297 0.487 0.363 0.553 ;
    END
  END A2
  PIN ZN
    DIRECTION OUTPUT ;
    USE SIGNAL ;
    ANTENNADIFFAREA 0.03888 ;
    PORT
      LAYER metal1 ;
        RECT 0.429 0.087 0.495 0.713 ;
    END
  END ZN
  PIN VDD
    DIRECTION INOUT ;
    USE POWER ;
    PORT
      LAYER metal0 ;
        RECT -0.066 0.74 0.594 0.86 ;
    END
  END VDD
  PIN VSS
    DIRECTION INOUT ;
    USE GROUND ;
    PORT
      LAYER metal0 ;
        RECT -0.066 -0.06 0.594 0.06 ;
    END
  END VSS
  OBS
    LAYER metal1 ;
      RECT 0.165 0.087 0.231 0.713 ;
    LAYER metal0 ;
      RECT 0.046 0.66 0.416 0.7 ;
      RECT 0.178 0.1 0.218 0.14 ;
      RECT 0.046 0.58 0.152 0.62 ;
      RECT 0.244 0.5 0.35 0.54 ;
      RECT 0.442 0.1 0.482 0.14 ;
      RECT 0.442 0.66 0.482 0.7 ;
  END
END OR2_X1

MACRO OR2_X2
  CLASS CORE ;
  FOREIGN OR2_X2 0 0 ;
  SIZE 0.792 BY 0.8 ;
  ORIGIN 0.0 0.0 ;
  SYMMETRY X Y ;
  PIN A1
    DIRECTION INPUT ;
    USE SIGNAL ;
    ANTENNAGATEAREA 0.008640 ;
    PORT
      LAYER metal1 ;
        RECT 0.165 0.167 0.231 0.233 ;
    END
  END A1
  PIN A2
    DIRECTION INPUT ;
    USE SIGNAL ;
    ANTENNAGATEAREA 0.008640 ;
    PORT
      LAYER metal1 ;
        RECT 0.165 0.487 0.231 0.553 ;
    END
  END A2
  PIN ZN
    DIRECTION OUTPUT ;
    USE SIGNAL ;
    ANTENNADIFFAREA 0.03888 ;
    PORT
      LAYER metal1 ;
        RECT 0.561 0.087 0.627 0.713 ;
    END
  END ZN
  PIN VDD
    DIRECTION INOUT ;
    USE POWER ;
    PORT
      LAYER metal0 ;
        RECT -0.066 0.74 0.858 0.86 ;
    END
  END VDD
  PIN VSS
    DIRECTION INOUT ;
    USE GROUND ;
    PORT
      LAYER metal0 ;
        RECT -0.066 -0.06 0.858 0.06 ;
    END
  END VSS
  OBS
    LAYER metal1 ;
      RECT 0.297 0.087 0.363 0.713 ;
    LAYER metal0 ;
      RECT 0.31 0.58 0.68 0.62 ;
      RECT 0.178 0.1 0.35 0.14 ;
      RECT 0.31 0.66 0.35 0.7 ;
      RECT 0.178 0.18 0.284 0.22 ;
      RECT 0.112 0.5 0.218 0.54 ;
      RECT 0.574 0.1 0.614 0.14 ;
      RECT 0.574 0.66 0.614 0.7 ;
  END
END OR2_X2

MACRO OR2_X4
  CLASS CORE ;
  FOREIGN OR2_X4 0 0 ;
  SIZE 1.056 BY 0.8 ;
  ORIGIN 0.0 0.0 ;
  SYMMETRY X Y ;
  PIN A1
    DIRECTION INPUT ;
    USE SIGNAL ;
    ANTENNAGATEAREA 0.017280 ;
    PORT
      LAYER metal1 ;
        RECT 0.165 0.487 0.231 0.553 ;
    END
  END A1
  PIN A2
    DIRECTION INPUT ;
    USE SIGNAL ;
    ANTENNAGATEAREA 0.017280 ;
    PORT
      LAYER metal1 ;
        RECT 0.297 0.407 0.363 0.553 ;
    END
  END A2
  PIN ZN
    DIRECTION OUTPUT ;
    USE SIGNAL ;
    ANTENNADIFFAREA 0.07776 ;
    PORT
      LAYER metal1 ;
        RECT 0.693 0.167 0.759 0.713 ;
        RECT 0.957 0.087 1.023 0.713 ;
    END
  END ZN
  PIN VDD
    DIRECTION INOUT ;
    USE POWER ;
    PORT
      LAYER metal0 ;
        RECT -0.066 0.74 1.122 0.86 ;
    END
  END VDD
  PIN VSS
    DIRECTION INOUT ;
    USE GROUND ;
    PORT
      LAYER metal0 ;
        RECT -0.066 -0.06 1.122 0.06 ;
    END
  END VSS
  OBS
    LAYER metal1 ;
      RECT 0.429 0.087 0.495 0.713 ;
      RECT 0.165 0.567 0.231 0.713 ;
      RECT 0.297 0.567 0.363 0.713 ;
      RECT 0.561 0.567 0.627 0.713 ;
    LAYER metal0 ;
      RECT 0.046 0.1 0.944 0.14 ;
      RECT 0.046 0.66 0.218 0.7 ;
      RECT 0.178 0.58 0.614 0.62 ;
      RECT 0.442 0.66 0.482 0.7 ;
      RECT 0.31 0.66 0.35 0.7 ;
      RECT 0.574 0.66 0.614 0.7 ;
      RECT 0.112 0.5 0.284 0.54 ;
      RECT 0.31 0.5 0.548 0.54 ;
      RECT 0.31 0.42 0.416 0.46 ;
      RECT 0.706 0.26 1.01 0.3 ;
      RECT 0.706 0.66 0.746 0.7 ;
      RECT 0.706 0.18 0.746 0.22 ;
      RECT 0.97 0.66 1.01 0.7 ;
      RECT 0.97 0.1 1.01 0.14 ;
  END
END OR2_X4

MACRO OR3_X1
  CLASS CORE ;
  FOREIGN OR3_X1 0 0 ;
  SIZE 0.792 BY 0.8 ;
  ORIGIN 0.0 0.0 ;
  SYMMETRY X Y ;
  PIN A1
    DIRECTION INPUT ;
    USE SIGNAL ;
    ANTENNAGATEAREA 0.008640 ;
    PORT
      LAYER metal1 ;
        RECT 0.429 0.327 0.495 0.553 ;
    END
  END A1
  PIN A2
    DIRECTION INPUT ;
    USE SIGNAL ;
    ANTENNAGATEAREA 0.008640 ;
    PORT
      LAYER metal1 ;
        RECT 0.561 0.327 0.627 0.473 ;
    END
  END A2
  PIN A3
    DIRECTION INPUT ;
    USE SIGNAL ;
    ANTENNAGATEAREA 0.008640 ;
    PORT
      LAYER metal1 ;
        RECT 0.297 0.567 0.363 0.633 ;
    END
  END A3
  PIN ZN
    DIRECTION OUTPUT ;
    USE SIGNAL ;
    ANTENNADIFFAREA 0.03888 ;
    PORT
      LAYER metal1 ;
        RECT 0.033 0.087 0.099 0.713 ;
    END
  END ZN
  PIN VDD
    DIRECTION INOUT ;
    USE POWER ;
    PORT
      LAYER metal0 ;
        RECT -0.066 0.74 0.858 0.86 ;
    END
  END VDD
  PIN VSS
    DIRECTION INOUT ;
    USE GROUND ;
    PORT
      LAYER metal0 ;
        RECT -0.066 -0.06 0.858 0.06 ;
    END
  END VSS
  OBS
    LAYER metal1 ;
      RECT 0.429 0.087 0.495 0.233 ;
      RECT 0.693 0.087 0.759 0.713 ;
    LAYER metal0 ;
      RECT 0.112 0.18 0.746 0.22 ;
      RECT 0.706 0.66 0.746 0.7 ;
      RECT 0.442 0.1 0.482 0.14 ;
      RECT 0.706 0.1 0.746 0.14 ;
      RECT 0.442 0.34 0.548 0.38 ;
      RECT 0.442 0.5 0.68 0.54 ;
      RECT 0.508 0.42 0.614 0.46 ;
      RECT 0.574 0.34 0.68 0.38 ;
      RECT 0.31 0.58 0.416 0.62 ;
      RECT 0.046 0.1 0.218 0.14 ;
      RECT 0.046 0.66 0.086 0.7 ;
  END
END OR3_X1

MACRO XNOR2_X1
  CLASS CORE ;
  FOREIGN XNOR2_X1 0 0 ;
  SIZE 0.792 BY 0.8 ;
  ORIGIN 0.0 0.0 ;
  SYMMETRY X Y ;
  PIN A
    DIRECTION INPUT ;
    USE SIGNAL ;
    ANTENNAGATEAREA 0.017280 ;
    PORT
      LAYER metal1 ;
        RECT 0.429 0.327 0.495 0.393 ;
    END
  END A
  PIN B
    DIRECTION INPUT ;
    USE SIGNAL ;
    ANTENNAGATEAREA 0.017280 ;
    PORT
      LAYER metal1 ;
        RECT 0.297 0.247 0.363 0.313 ;
    END
  END B
  PIN ZN
    DIRECTION OUTPUT ;
    USE SIGNAL ;
    ANTENNADIFFAREA 0.03888 ;
    PORT
      LAYER metal1 ;
        RECT 0.561 0.167 0.627 0.713 ;
    END
  END ZN
  PIN VDD
    DIRECTION INOUT ;
    USE POWER ;
    PORT
      LAYER metal0 ;
        RECT -0.066 0.74 0.858 0.86 ;
    END
  END VDD
  PIN VSS
    DIRECTION INOUT ;
    USE GROUND ;
    PORT
      LAYER metal0 ;
        RECT -0.066 -0.06 0.858 0.06 ;
    END
  END VSS
  OBS
    LAYER metal1 ;
      RECT 0.033 0.087 0.099 0.713 ;
    LAYER metal0 ;
      RECT 0.442 0.1 0.746 0.14 ;
      RECT 0.046 0.66 0.416 0.7 ;
      RECT 0.046 0.1 0.086 0.14 ;
      RECT 0.112 0.34 0.548 0.38 ;
      RECT 0.244 0.26 0.68 0.3 ;
      RECT 0.442 0.66 0.614 0.7 ;
      RECT 0.574 0.18 0.614 0.22 ;
  END
END XNOR2_X1

MACRO XNOR2_X2
  CLASS CORE ;
  FOREIGN XNOR2_X2 0 0 ;
  SIZE 0.66 BY 1.6 ;
  ORIGIN 0.0 0.0 ;
  SYMMETRY X Y ;
  PIN A
    DIRECTION INPUT ;
    USE SIGNAL ;
    ANTENNAGATEAREA 0.025920 ;
    PORT
      LAYER metal1 ;
        RECT 0.165 0.647 0.231 1.033 ;
    END
  END A
  PIN B
    DIRECTION INPUT ;
    USE SIGNAL ;
    ANTENNAGATEAREA 0.025920 ;
    PORT
      LAYER metal1 ;
        RECT 0.561 0.487 0.627 1.113 ;
    END
  END B
  PIN ZN
    DIRECTION OUTPUT ;
    USE SIGNAL ;
    ANTENNADIFFAREA 0.03888 ;
    PORT
      LAYER metal1 ;
        RECT 0.297 0.087 0.363 0.713 ;
    END
  END ZN
  PIN VDD
    DIRECTION INOUT ;
    USE POWER ;
    PORT
      LAYER metal0 ;
        RECT -0.066 1.54 0.726 1.66 ;
        RECT -0.066 -0.06 0.726 0.06 ;
    END
  END VDD
  PIN VSS
    DIRECTION INOUT ;
    USE GROUND ;
    PORT
      LAYER metal0 ;
        RECT -0.066 0.74 0.726 0.86 ;
    END
  END VSS
  OBS
    LAYER metal1 ;
      RECT 0.429 0.567 0.495 0.713 ;
      RECT 0.033 0.647 0.099 1.193 ;
      RECT 0.165 1.127 0.231 1.513 ;
      RECT 0.429 0.967 0.495 1.513 ;
    LAYER metal0 ;
      RECT 0.046 0.9 0.614 0.94 ;
      RECT 0.178 0.58 0.482 0.62 ;
      RECT 0.046 1.14 0.482 1.18 ;
      RECT 0.046 0.66 0.152 0.7 ;
      RECT 0.442 0.66 0.482 0.7 ;
      RECT 0.178 1.46 0.218 1.5 ;
      RECT 0.442 1.46 0.482 1.5 ;
      RECT 0.442 0.98 0.482 1.02 ;
      RECT 0.112 0.98 0.284 1.02 ;
      RECT 0.178 0.66 0.284 0.7 ;
      RECT 0.376 0.5 0.614 0.54 ;
      RECT 0.376 1.06 0.614 1.1 ;
      RECT 0.31 0.66 0.35 0.7 ;
      RECT 0.178 0.1 0.35 0.14 ;
  END
END XNOR2_X2

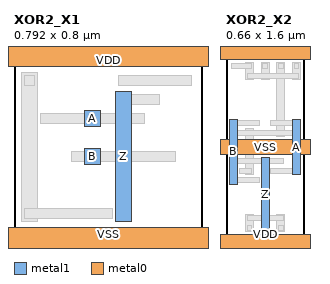
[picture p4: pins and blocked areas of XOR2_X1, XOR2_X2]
MACRO XOR2_X1
  CLASS CORE ;
  FOREIGN XOR2_X1 0 0 ;
  SIZE 0.792 BY 0.8 ;
  ORIGIN 0.0 0.0 ;
  SYMMETRY X Y ;
  PIN A
    DIRECTION INPUT ;
    USE SIGNAL ;
    ANTENNAGATEAREA 0.017280 ;
    PORT
      LAYER metal1 ;
        RECT 0.297 0.487 0.363 0.553 ;
    END
  END A
  PIN B
    DIRECTION INPUT ;
    USE SIGNAL ;
    ANTENNAGATEAREA 0.017280 ;
    PORT
      LAYER metal1 ;
        RECT 0.297 0.327 0.363 0.393 ;
    END
  END B
  PIN Z
    DIRECTION OUTPUT ;
    USE SIGNAL ;
    ANTENNADIFFAREA 0.03888 ;
    PORT
      LAYER metal1 ;
        RECT 0.429 0.087 0.495 0.633 ;
    END
  END Z
  PIN VDD
    DIRECTION INOUT ;
    USE POWER ;
    PORT
      LAYER metal0 ;
        RECT -0.066 0.74 0.858 0.86 ;
    END
  END VDD
  PIN VSS
    DIRECTION INOUT ;
    USE GROUND ;
    PORT
      LAYER metal0 ;
        RECT -0.066 -0.06 0.858 0.06 ;
    END
  END VSS
  OBS
    LAYER metal1 ;
      RECT 0.033 0.087 0.099 0.713 ;
    LAYER metal0 ;
      RECT 0.442 0.66 0.746 0.7 ;
      RECT 0.046 0.1 0.416 0.14 ;
      RECT 0.046 0.66 0.086 0.7 ;
      RECT 0.112 0.5 0.548 0.54 ;
      RECT 0.244 0.34 0.68 0.38 ;
      RECT 0.442 0.1 0.482 0.14 ;
      RECT 0.442 0.58 0.614 0.62 ;
  END
END XOR2_X1

MACRO XOR2_X2
  CLASS CORE ;
  FOREIGN XOR2_X2 0 0 ;
  SIZE 0.66 BY 1.6 ;
  ORIGIN 0.0 0.0 ;
  SYMMETRY X Y ;
  PIN A
    DIRECTION INPUT ;
    USE SIGNAL ;
    ANTENNAGATEAREA 0.025920 ;
    PORT
      LAYER metal1 ;
        RECT 0.561 0.567 0.627 1.033 ;
    END
  END A
  PIN B
    DIRECTION INPUT ;
    USE SIGNAL ;
    ANTENNAGATEAREA 0.025920 ;
    PORT
      LAYER metal1 ;
        RECT 0.033 0.487 0.099 1.033 ;
    END
  END B
  PIN Z
    DIRECTION OUTPUT ;
    USE SIGNAL ;
    ANTENNADIFFAREA 0.05832 ;
    PORT
      LAYER metal1 ;
        RECT 0.297 0.087 0.363 0.713 ;
    END
  END Z
  PIN VDD
    DIRECTION INOUT ;
    USE POWER ;
    PORT
      LAYER metal0 ;
        RECT -0.066 1.54 0.726 1.66 ;
        RECT -0.066 -0.06 0.726 0.06 ;
    END
  END VDD
  PIN VSS
    DIRECTION INOUT ;
    USE GROUND ;
    PORT
      LAYER metal0 ;
        RECT -0.066 0.74 0.726 0.86 ;
    END
  END VSS
  OBS
    LAYER metal1 ;
      RECT 0.165 0.567 0.231 0.953 ;
      RECT 0.429 0.887 0.495 1.513 ;
      RECT 0.165 0.087 0.231 0.233 ;
      RECT 0.429 0.087 0.495 0.233 ;
      RECT 0.165 1.367 0.231 1.513 ;
      RECT 0.297 1.367 0.363 1.513 ;
      RECT 0.561 1.367 0.627 1.513 ;
    LAYER metal0 ;
      RECT 0.046 0.9 0.614 0.94 ;
      RECT 0.112 0.58 0.218 0.62 ;
      RECT 0.178 0.18 0.482 0.22 ;
      RECT 0.046 1.46 0.218 1.5 ;
      RECT 0.178 1.38 0.614 1.42 ;
      RECT 0.442 1.46 0.482 1.5 ;
      RECT 0.178 0.1 0.218 0.14 ;
      RECT 0.442 0.1 0.482 0.14 ;
      RECT 0.31 1.46 0.35 1.5 ;
      RECT 0.574 1.46 0.614 1.5 ;
      RECT 0.376 0.58 0.614 0.62 ;
      RECT 0.376 0.98 0.614 1.02 ;
      RECT 0.046 0.5 0.284 0.54 ;
      RECT 0.046 0.98 0.284 1.02 ;
      RECT 0.046 0.66 0.482 0.7 ;
      RECT 0.31 0.1 0.35 0.14 ;
  END
END XOR2_X2

END LIBRARY
